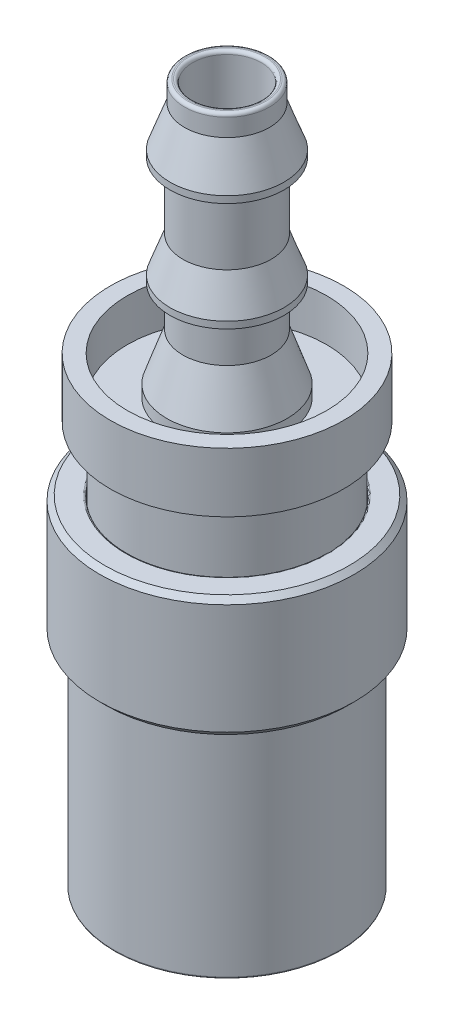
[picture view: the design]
ISO-10303-21;
HEADER;
FILE_DESCRIPTION(('STEP AP214'),'2;1');
FILE_NAME('part.step','',(''),(''),'','','');
FILE_SCHEMA(('AUTOMOTIVE_DESIGN { 1 0 10303 214 1 1 1 1 }'));
ENDSEC;
DATA;
#1=APPLICATION_CONTEXT('core data for automotive mechanical design processes');
#2=APPLICATION_PROTOCOL_DEFINITION('international standard','automotive_design',2000,#1);
#3=PRODUCT_CONTEXT('',#1,'mechanical');
#4=PRODUCT('Part','Part','',(#3));
#5=PRODUCT_RELATED_PRODUCT_CATEGORY('part','',(#4));
#6=PRODUCT_DEFINITION_FORMATION('','',#4);
#7=PRODUCT_DEFINITION_CONTEXT('part definition',#1,'design');
#8=PRODUCT_DEFINITION('design','',#6,#7);
#9=PRODUCT_DEFINITION_SHAPE('','',#8);
#10=(LENGTH_UNIT() NAMED_UNIT(*) SI_UNIT(.MILLI.,.METRE.));
#11=(NAMED_UNIT(*) PLANE_ANGLE_UNIT() SI_UNIT($,.RADIAN.));
#12=(NAMED_UNIT(*) SI_UNIT($,.STERADIAN.) SOLID_ANGLE_UNIT());
#13=UNCERTAINTY_MEASURE_WITH_UNIT(LENGTH_MEASURE(1.E-05),#10,'distance_accuracy_value','');
#14=(GEOMETRIC_REPRESENTATION_CONTEXT(3) GLOBAL_UNCERTAINTY_ASSIGNED_CONTEXT((#13)) GLOBAL_UNIT_ASSIGNED_CONTEXT((#10,
#11,#12)) REPRESENTATION_CONTEXT('',''));
#15=CARTESIAN_POINT('',(0.,0.,0.));
#16=DIRECTION('',(0.,0.,1.));
#17=DIRECTION('',(1.,0.,0.));
#18=AXIS2_PLACEMENT_3D('',#15,#16,#17);
#19=CARTESIAN_POINT('',(0.,25.2095,0.));
#20=DIRECTION('',(0.,-1.,0.));
#21=DIRECTION('',(0.,0.,-1.));
#22=AXIS2_PLACEMENT_3D('',#19,#20,#21);
#23=CONICAL_SURFACE('',#22,9.3345,0.785398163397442);
#24=CARTESIAN_POINT('',(0.,25.4,0.));
#25=DIRECTION('',(0.,-1.,0.));
#26=DIRECTION('',(0.,0.,-1.));
#27=AXIS2_PLACEMENT_3D('',#24,#25,#26);
#28=CIRCLE('',#27,9.144);
#29=CARTESIAN_POINT('',(0.,25.4,9.144));
#30=VERTEX_POINT('',#29);
#31=EDGE_CURVE('P0_E11',#30,#30,#28,.T.);
#32=ORIENTED_EDGE('',*,*,#31,.T.);
#33=DIRECTION('',(0.,-0.707106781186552,0.707106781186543));
#34=VECTOR('',#33,1.);
#35=CARTESIAN_POINT('',(0.,25.2095,9.3345));
#36=LINE('',#35,#34);
#37=CARTESIAN_POINT('',(0.,25.019,9.525));
#38=VERTEX_POINT('',#37);
#39=EDGE_CURVE('P0_E27',#30,#38,#36,.T.);
#40=ORIENTED_EDGE('',*,*,#39,.T.);
#41=CARTESIAN_POINT('',(0.,25.019,0.));
#42=DIRECTION('',(0.,1.,0.));
#43=DIRECTION('',(0.,0.,-1.));
#44=AXIS2_PLACEMENT_3D('',#41,#42,#43);
#45=CIRCLE('',#44,9.525);
#46=CARTESIAN_POINT('',(0.,25.019,-9.525));
#47=VERTEX_POINT('',#46);
#48=EDGE_CURVE('P0_E226',#38,#47,#45,.T.);
#49=ORIENTED_EDGE('',*,*,#48,.T.);
#50=CARTESIAN_POINT('',(0.,25.019,0.));
#51=DIRECTION('',(0.,1.,0.));
#52=DIRECTION('',(0.,0.,-1.));
#53=AXIS2_PLACEMENT_3D('',#50,#51,#52);
#54=CIRCLE('',#53,9.525);
#55=EDGE_CURVE('P0_E207',#47,#38,#54,.T.);
#56=ORIENTED_EDGE('',*,*,#55,.T.);
#57=ORIENTED_EDGE('',*,*,#39,.F.);
#58=EDGE_LOOP('',(#32,#40,#49,#56,#57));
#59=FACE_BOUND('',#58,.T.);
#60=ADVANCED_FACE('P0_F16',(#59),#23,.T.);
#61=CARTESIAN_POINT('',(0.,20.828,0.));
#62=DIRECTION('',(0.,1.,0.));
#63=DIRECTION('',(0.,0.,1.));
#64=AXIS2_PLACEMENT_3D('',#61,#62,#63);
#65=CYLINDRICAL_SURFACE('',#64,9.525);
#66=ORIENTED_EDGE('',*,*,#48,.F.);
#67=ORIENTED_EDGE('',*,*,#55,.F.);
#68=DIRECTION('',(0.,-1.,0.));
#69=VECTOR('',#68,1.);
#70=CARTESIAN_POINT('',(0.,20.828,-9.525));
#71=LINE('',#70,#69);
#72=CARTESIAN_POINT('',(0.,16.764,-9.525));
#73=VERTEX_POINT('',#72);
#74=EDGE_CURVE('P0_E203',#47,#73,#71,.T.);
#75=ORIENTED_EDGE('',*,*,#74,.T.);
#76=CARTESIAN_POINT('',(0.,16.764,0.));
#77=DIRECTION('',(0.,-1.,0.));
#78=DIRECTION('',(0.,0.,-1.));
#79=AXIS2_PLACEMENT_3D('',#76,#77,#78);
#80=CIRCLE('',#79,9.525);
#81=CARTESIAN_POINT('',(0.,16.764,9.525));
#82=VERTEX_POINT('',#81);
#83=EDGE_CURVE('P0_E274',#82,#73,#80,.T.);
#84=ORIENTED_EDGE('',*,*,#83,.F.);
#85=CARTESIAN_POINT('',(0.,16.764,0.));
#86=DIRECTION('',(0.,-1.,0.));
#87=DIRECTION('',(0.,0.,-1.));
#88=AXIS2_PLACEMENT_3D('',#85,#86,#87);
#89=CIRCLE('',#88,9.525);
#90=EDGE_CURVE('P0_E301',#73,#82,#89,.T.);
#91=ORIENTED_EDGE('',*,*,#90,.F.);
#92=ORIENTED_EDGE('',*,*,#74,.F.);
#93=EDGE_LOOP('',(#66,#67,#75,#84,#91,#92));
#94=FACE_BOUND('',#93,.T.);
#95=ADVANCED_FACE('P0_F344',(#94),#65,.T.);
#96=CARTESIAN_POINT('',(0.,25.4,7.4549));
#97=DIRECTION('',(0.,1.,0.));
#98=DIRECTION('',(1.,0.,0.));
#99=AXIS2_PLACEMENT_3D('',#96,#97,#98);
#100=PLANE('',#99);
#101=ORIENTED_EDGE('',*,*,#31,.F.);
#102=EDGE_LOOP('',(#101));
#103=FACE_BOUND('',#102,.T.);
#104=CARTESIAN_POINT('',(0.,25.4,0.));
#105=DIRECTION('',(0.,1.,0.));
#106=DIRECTION('',(0.,0.,-1.));
#107=AXIS2_PLACEMENT_3D('',#104,#105,#106);
#108=CIRCLE('',#107,7.5819);
#109=CARTESIAN_POINT('',(0.,25.4,-7.5819));
#110=VERTEX_POINT('',#109);
#111=EDGE_CURVE('P0_E138',#110,#110,#108,.T.);
#112=ORIENTED_EDGE('',*,*,#111,.F.);
#113=EDGE_LOOP('',(#112));
#114=FACE_BOUND('',#113,.T.);
#115=ADVANCED_FACE('P0_F139',(#103,#114),#100,.T.);
#116=CARTESIAN_POINT('',(0.,6.096,0.));
#117=DIRECTION('',(0.,1.,0.));
#118=DIRECTION('',(0.,0.,1.));
#119=AXIS2_PLACEMENT_3D('',#116,#117,#118);
#120=TOROIDAL_SURFACE('',#119,6.6802,0.254);
#121=CARTESIAN_POINT('',(0.,6.096,0.));
#122=DIRECTION('',(0.,-1.,0.));
#123=DIRECTION('',(0.,0.,-1.));
#124=AXIS2_PLACEMENT_3D('',#121,#122,#123);
#125=CIRCLE('',#124,6.4262);
#126=CARTESIAN_POINT('',(0.,6.096,6.4262));
#127=VERTEX_POINT('',#126);
#128=CARTESIAN_POINT('',(0.,6.096,-6.4262));
#129=VERTEX_POINT('',#128);
#130=EDGE_CURVE('P0_E208',#127,#129,#125,.T.);
#131=ORIENTED_EDGE('',*,*,#130,.T.);
#132=CARTESIAN_POINT('',(0.,6.096,-6.6802));
#133=DIRECTION('',(-1.,0.,0.));
#134=DIRECTION('',(0.,0.,-1.));
#135=AXIS2_PLACEMENT_3D('',#132,#133,#134);
#136=CIRCLE('',#135,0.254);
#137=CARTESIAN_POINT('',(0.,6.35,-6.6802));
#138=VERTEX_POINT('',#137);
#139=EDGE_CURVE('P0_E253',#129,#138,#136,.T.);
#140=ORIENTED_EDGE('',*,*,#139,.T.);
#141=CARTESIAN_POINT('',(0.,6.35,0.));
#142=DIRECTION('',(0.,1.,0.));
#143=DIRECTION('',(0.,0.,-1.));
#144=AXIS2_PLACEMENT_3D('',#141,#142,#143);
#145=CIRCLE('',#144,6.6802);
#146=CARTESIAN_POINT('',(0.,6.35,6.6802));
#147=VERTEX_POINT('',#146);
#148=EDGE_CURVE('P0_E248',#138,#147,#145,.T.);
#149=ORIENTED_EDGE('',*,*,#148,.T.);
#150=CARTESIAN_POINT('',(0.,6.35,0.));
#151=DIRECTION('',(0.,1.,0.));
#152=DIRECTION('',(0.,0.,-1.));
#153=AXIS2_PLACEMENT_3D('',#150,#151,#152);
#154=CIRCLE('',#153,6.6802);
#155=EDGE_CURVE('P0_E244',#147,#138,#154,.T.);
#156=ORIENTED_EDGE('',*,*,#155,.T.);
#157=ORIENTED_EDGE('',*,*,#139,.F.);
#158=CARTESIAN_POINT('',(0.,6.096,0.));
#159=DIRECTION('',(0.,-1.,0.));
#160=DIRECTION('',(0.,0.,-1.));
#161=AXIS2_PLACEMENT_3D('',#158,#159,#160);
#162=CIRCLE('',#161,6.4262);
#163=EDGE_CURVE('P0_E249',#129,#127,#162,.T.);
#164=ORIENTED_EDGE('',*,*,#163,.T.);
#165=EDGE_LOOP('',(#131,#140,#149,#156,#157,#164));
#166=FACE_BOUND('',#165,.T.);
#167=ADVANCED_FACE('P0_F18',(#166),#120,.T.);
#168=CARTESIAN_POINT('',(0.,6.35,6.4262));
#169=DIRECTION('',(0.,1.,0.));
#170=DIRECTION('',(1.,0.,0.));
#171=AXIS2_PLACEMENT_3D('',#168,#169,#170);
#172=PLANE('',#171);
#173=CARTESIAN_POINT('',(0.,6.35,0.));
#174=DIRECTION('',(0.,-1.,0.));
#175=DIRECTION('',(0.,0.,-1.));
#176=AXIS2_PLACEMENT_3D('',#173,#174,#175);
#177=CIRCLE('',#176,7.2009);
#178=CARTESIAN_POINT('',(0.,6.35,7.2009));
#179=VERTEX_POINT('',#178);
#180=CARTESIAN_POINT('',(0.,6.35,-7.2009));
#181=VERTEX_POINT('',#180);
#182=EDGE_CURVE('P0_E202',#179,#181,#177,.T.);
#183=ORIENTED_EDGE('',*,*,#182,.F.);
#184=CARTESIAN_POINT('',(0.,6.35,0.));
#185=DIRECTION('',(0.,-1.,0.));
#186=DIRECTION('',(0.,0.,-1.));
#187=AXIS2_PLACEMENT_3D('',#184,#185,#186);
#188=CIRCLE('',#187,7.2009);
#189=EDGE_CURVE('P0_E198',#181,#179,#188,.T.);
#190=ORIENTED_EDGE('',*,*,#189,.F.);
#191=EDGE_LOOP('',(#183,#190));
#192=FACE_BOUND('',#191,.T.);
#193=ORIENTED_EDGE('',*,*,#155,.F.);
#194=ORIENTED_EDGE('',*,*,#148,.F.);
#195=EDGE_LOOP('',(#193,#194));
#196=FACE_BOUND('',#195,.T.);
#197=ADVANCED_FACE('P0_F440',(#192,#196),#172,.T.);
#198=CARTESIAN_POINT('',(0.,4.1402,0.));
#199=DIRECTION('',(0.,1.,0.));
#200=DIRECTION('',(0.,0.,1.));
#201=AXIS2_PLACEMENT_3D('',#198,#199,#200);
#202=CYLINDRICAL_SURFACE('',#201,6.4262);
#203=ORIENTED_EDGE('',*,*,#130,.F.);
#204=ORIENTED_EDGE('',*,*,#163,.F.);
#205=DIRECTION('',(0.,-1.,0.));
#206=VECTOR('',#205,1.);
#207=CARTESIAN_POINT('',(0.,4.1402,-6.4262));
#208=LINE('',#207,#206);
#209=CARTESIAN_POINT('',(0.,1.9304,-6.4262));
#210=VERTEX_POINT('',#209);
#211=EDGE_CURVE('P0_E288',#129,#210,#208,.T.);
#212=ORIENTED_EDGE('',*,*,#211,.T.);
#213=CARTESIAN_POINT('',(0.,1.9304,0.));
#214=DIRECTION('',(0.,1.,0.));
#215=DIRECTION('',(1.,0.,0.));
#216=AXIS2_PLACEMENT_3D('',#213,#214,#215);
#217=CIRCLE('',#216,6.4262);
#218=CARTESIAN_POINT('',(0.,1.9304,6.4262));
#219=VERTEX_POINT('',#218);
#220=EDGE_CURVE('P0_E254',#219,#210,#217,.T.);
#221=ORIENTED_EDGE('',*,*,#220,.F.);
#222=CARTESIAN_POINT('',(0.,1.9304,0.));
#223=DIRECTION('',(0.,1.,0.));
#224=DIRECTION('',(1.,0.,0.));
#225=AXIS2_PLACEMENT_3D('',#222,#223,#224);
#226=CIRCLE('',#225,6.4262);
#227=EDGE_CURVE('P0_E209',#210,#219,#226,.T.);
#228=ORIENTED_EDGE('',*,*,#227,.F.);
#229=ORIENTED_EDGE('',*,*,#211,.F.);
#230=EDGE_LOOP('',(#203,#204,#212,#221,#228,#229));
#231=FACE_BOUND('',#230,.T.);
#232=ADVANCED_FACE('P0_F420',(#231),#202,.F.);
#233=CARTESIAN_POINT('',(0.,6.604,0.));
#234=DIRECTION('',(0.,1.,0.));
#235=DIRECTION('',(0.,0.,1.));
#236=AXIS2_PLACEMENT_3D('',#233,#234,#235);
#237=TOROIDAL_SURFACE('',#236,7.2009,0.254);
#238=CARTESIAN_POINT('',(0.,6.604,0.));
#239=DIRECTION('',(0.,1.,0.));
#240=DIRECTION('',(0.,0.,-1.));
#241=AXIS2_PLACEMENT_3D('',#238,#239,#240);
#242=CIRCLE('',#241,7.4549);
#243=CARTESIAN_POINT('',(0.,6.604,7.4549));
#244=VERTEX_POINT('',#243);
#245=CARTESIAN_POINT('',(0.,6.604,-7.4549));
#246=VERTEX_POINT('',#245);
#247=EDGE_CURVE('P0_E285',#244,#246,#242,.T.);
#248=ORIENTED_EDGE('',*,*,#247,.T.);
#249=CARTESIAN_POINT('',(0.,6.604,-7.2009));
#250=DIRECTION('',(-1.,0.,0.));
#251=DIRECTION('',(0.,0.,-1.));
#252=AXIS2_PLACEMENT_3D('',#249,#250,#251);
#253=CIRCLE('',#252,0.254);
#254=EDGE_CURVE('P0_E201',#246,#181,#253,.T.);
#255=ORIENTED_EDGE('',*,*,#254,.T.);
#256=ORIENTED_EDGE('',*,*,#189,.T.);
#257=ORIENTED_EDGE('',*,*,#182,.T.);
#258=ORIENTED_EDGE('',*,*,#254,.F.);
#259=CARTESIAN_POINT('',(0.,6.604,0.));
#260=DIRECTION('',(0.,1.,0.));
#261=DIRECTION('',(0.,0.,-1.));
#262=AXIS2_PLACEMENT_3D('',#259,#260,#261);
#263=CIRCLE('',#262,7.4549);
#264=EDGE_CURVE('P0_E281',#246,#244,#263,.T.);
#265=ORIENTED_EDGE('',*,*,#264,.T.);
#266=EDGE_LOOP('',(#248,#255,#256,#257,#258,#265));
#267=FACE_BOUND('',#266,.T.);
#268=ADVANCED_FACE('P0_F413',(#267),#237,.F.);
#269=CARTESIAN_POINT('',(0.,15.875,0.));
#270=DIRECTION('',(0.,1.,0.));
#271=DIRECTION('',(0.,0.,1.));
#272=AXIS2_PLACEMENT_3D('',#269,#270,#271);
#273=CYLINDRICAL_SURFACE('',#272,7.4549);
#274=CARTESIAN_POINT('',(0.,25.273,0.));
#275=DIRECTION('',(0.,-1.,0.));
#276=DIRECTION('',(0.,0.,-1.));
#277=AXIS2_PLACEMENT_3D('',#274,#275,#276);
#278=CIRCLE('',#277,7.4549);
#279=CARTESIAN_POINT('',(0.,25.273,7.4549));
#280=VERTEX_POINT('',#279);
#281=CARTESIAN_POINT('',(0.,25.273,-7.4549));
#282=VERTEX_POINT('',#281);
#283=EDGE_CURVE('P0_E151',#280,#282,#278,.T.);
#284=ORIENTED_EDGE('',*,*,#283,.F.);
#285=CARTESIAN_POINT('',(0.,25.273,0.));
#286=DIRECTION('',(0.,-1.,0.));
#287=DIRECTION('',(0.,0.,-1.));
#288=AXIS2_PLACEMENT_3D('',#285,#286,#287);
#289=CIRCLE('',#288,7.4549);
#290=EDGE_CURVE('P0_E145',#282,#280,#289,.T.);
#291=ORIENTED_EDGE('',*,*,#290,.F.);
#292=DIRECTION('',(0.,-1.,0.));
#293=VECTOR('',#292,1.);
#294=CARTESIAN_POINT('',(0.,15.875,-7.4549));
#295=LINE('',#294,#293);
#296=EDGE_CURVE('P0_E277',#282,#246,#295,.T.);
#297=ORIENTED_EDGE('',*,*,#296,.T.);
#298=ORIENTED_EDGE('',*,*,#247,.F.);
#299=ORIENTED_EDGE('',*,*,#264,.F.);
#300=ORIENTED_EDGE('',*,*,#296,.F.);
#301=EDGE_LOOP('',(#284,#291,#297,#298,#299,#300));
#302=FACE_BOUND('',#301,.T.);
#303=ADVANCED_FACE('P0_F419',(#302),#273,.F.);
#304=CARTESIAN_POINT('',(0.,16.51,0.));
#305=DIRECTION('',(0.,1.,0.));
#306=DIRECTION('',(0.,0.,-1.));
#307=AXIS2_PLACEMENT_3D('',#304,#305,#306);
#308=CONICAL_SURFACE('',#307,9.271,0.785398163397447);
#309=ORIENTED_EDGE('',*,*,#83,.T.);
#310=ORIENTED_EDGE('',*,*,#90,.T.);
#311=DIRECTION('',(0.,-0.707106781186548,-0.707106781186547));
#312=VECTOR('',#311,1.);
#313=CARTESIAN_POINT('',(0.,16.51,9.271));
#314=LINE('',#313,#312);
#315=CARTESIAN_POINT('',(0.,16.256,9.017));
#316=VERTEX_POINT('',#315);
#317=EDGE_CURVE('P0_E303',#82,#316,#314,.T.);
#318=ORIENTED_EDGE('',*,*,#317,.T.);
#319=CARTESIAN_POINT('',(0.,16.256,0.));
#320=DIRECTION('',(0.,1.,0.));
#321=DIRECTION('',(0.,0.,-1.));
#322=AXIS2_PLACEMENT_3D('',#319,#320,#321);
#323=CIRCLE('',#322,9.017);
#324=EDGE_CURVE('P0_E233',#316,#316,#323,.T.);
#325=ORIENTED_EDGE('',*,*,#324,.T.);
#326=ORIENTED_EDGE('',*,*,#317,.F.);
#327=EDGE_LOOP('',(#309,#310,#318,#325,#326));
#328=FACE_BOUND('',#327,.T.);
#329=ADVANCED_FACE('P0_F321',(#328),#308,.T.);
#330=CARTESIAN_POINT('',(0.,16.256,9.525));
#331=DIRECTION('',(0.,-1.,0.));
#332=DIRECTION('',(0.,0.,-1.));
#333=AXIS2_PLACEMENT_3D('',#330,#331,#332);
#334=PLANE('',#333);
#335=ORIENTED_EDGE('',*,*,#324,.F.);
#336=EDGE_LOOP('',(#335));
#337=FACE_BOUND('',#336,.T.);
#338=CARTESIAN_POINT('',(0.,16.256,0.));
#339=DIRECTION('',(0.,1.,0.));
#340=DIRECTION('',(1.,0.,0.));
#341=AXIS2_PLACEMENT_3D('',#338,#339,#340);
#342=CIRCLE('',#341,8.4328);
#343=CARTESIAN_POINT('',(0.,16.256,8.4328));
#344=VERTEX_POINT('',#343);
#345=CARTESIAN_POINT('',(0.,16.256,-8.4328));
#346=VERTEX_POINT('',#345);
#347=EDGE_CURVE('P0_E230',#344,#346,#342,.T.);
#348=ORIENTED_EDGE('',*,*,#347,.T.);
#349=CARTESIAN_POINT('',(0.,16.256,0.));
#350=DIRECTION('',(0.,1.,0.));
#351=DIRECTION('',(1.,0.,0.));
#352=AXIS2_PLACEMENT_3D('',#349,#350,#351);
#353=CIRCLE('',#352,8.4328);
#354=EDGE_CURVE('P0_E234',#346,#344,#353,.T.);
#355=ORIENTED_EDGE('',*,*,#354,.T.);
#356=EDGE_LOOP('',(#348,#355));
#357=FACE_BOUND('',#356,.T.);
#358=ADVANCED_FACE('P0_F324',(#337,#357),#334,.T.);
#359=CARTESIAN_POINT('',(0.,0.127,0.));
#360=DIRECTION('',(0.,1.,0.));
#361=DIRECTION('',(0.,0.,1.));
#362=AXIS2_PLACEMENT_3D('',#359,#360,#361);
#363=TOROIDAL_SURFACE('',#362,8.3058,0.127);
#364=CARTESIAN_POINT('',(0.,0.127,0.));
#365=DIRECTION('',(0.,-1.,0.));
#366=DIRECTION('',(0.,0.,-1.));
#367=AXIS2_PLACEMENT_3D('',#364,#365,#366);
#368=CIRCLE('',#367,8.4328);
#369=CARTESIAN_POINT('',(0.,0.127,8.4328));
#370=VERTEX_POINT('',#369);
#371=CARTESIAN_POINT('',(0.,0.127,-8.4328));
#372=VERTEX_POINT('',#371);
#373=EDGE_CURVE('P0_E243',#370,#372,#368,.T.);
#374=ORIENTED_EDGE('',*,*,#373,.T.);
#375=CARTESIAN_POINT('',(0.,0.127,-8.3058));
#376=DIRECTION('',(-1.,0.,0.));
#377=DIRECTION('',(0.,0.,-1.));
#378=AXIS2_PLACEMENT_3D('',#375,#376,#377);
#379=CIRCLE('',#378,0.127);
#380=CARTESIAN_POINT('',(0.,0.,-8.3058));
#381=VERTEX_POINT('',#380);
#382=EDGE_CURVE('P0_E192',#372,#381,#379,.T.);
#383=ORIENTED_EDGE('',*,*,#382,.T.);
#384=CARTESIAN_POINT('',(0.,0.,0.));
#385=DIRECTION('',(0.,1.,0.));
#386=DIRECTION('',(0.,0.,-1.));
#387=AXIS2_PLACEMENT_3D('',#384,#385,#386);
#388=CIRCLE('',#387,8.3058);
#389=CARTESIAN_POINT('',(0.,0.,8.3058));
#390=VERTEX_POINT('',#389);
#391=EDGE_CURVE('P0_E185',#381,#390,#388,.T.);
#392=ORIENTED_EDGE('',*,*,#391,.T.);
#393=CARTESIAN_POINT('',(0.,0.,0.));
#394=DIRECTION('',(0.,1.,0.));
#395=DIRECTION('',(0.,0.,-1.));
#396=AXIS2_PLACEMENT_3D('',#393,#394,#395);
#397=CIRCLE('',#396,8.3058);
#398=EDGE_CURVE('P0_E177',#390,#381,#397,.T.);
#399=ORIENTED_EDGE('',*,*,#398,.T.);
#400=ORIENTED_EDGE('',*,*,#382,.F.);
#401=CARTESIAN_POINT('',(0.,0.127,0.));
#402=DIRECTION('',(0.,-1.,0.));
#403=DIRECTION('',(0.,0.,-1.));
#404=AXIS2_PLACEMENT_3D('',#401,#402,#403);
#405=CIRCLE('',#404,8.4328);
#406=EDGE_CURVE('P0_E159',#372,#370,#405,.T.);
#407=ORIENTED_EDGE('',*,*,#406,.T.);
#408=EDGE_LOOP('',(#374,#383,#392,#399,#400,#407));
#409=FACE_BOUND('',#408,.T.);
#410=ADVANCED_FACE('P0_F327',(#409),#363,.T.);
#411=CARTESIAN_POINT('',(0.,0.,8.4328));
#412=DIRECTION('',(0.,-1.,0.));
#413=DIRECTION('',(0.,0.,-1.));
#414=AXIS2_PLACEMENT_3D('',#411,#412,#413);
#415=PLANE('',#414);
#416=ORIENTED_EDGE('',*,*,#398,.F.);
#417=ORIENTED_EDGE('',*,*,#391,.F.);
#418=EDGE_LOOP('',(#416,#417));
#419=FACE_BOUND('',#418,.T.);
#420=CARTESIAN_POINT('',(0.,0.,0.));
#421=DIRECTION('',(0.,-1.,0.));
#422=DIRECTION('',(0.,0.,-1.));
#423=AXIS2_PLACEMENT_3D('',#420,#421,#422);
#424=CIRCLE('',#423,7.4422);
#425=CARTESIAN_POINT('',(0.,0.,7.4422));
#426=VERTEX_POINT('',#425);
#427=CARTESIAN_POINT('',(0.,0.,-7.4422));
#428=VERTEX_POINT('',#427);
#429=EDGE_CURVE('P0_E155',#426,#428,#424,.T.);
#430=ORIENTED_EDGE('',*,*,#429,.F.);
#431=CARTESIAN_POINT('',(0.,0.,0.));
#432=DIRECTION('',(0.,-1.,0.));
#433=DIRECTION('',(0.,0.,-1.));
#434=AXIS2_PLACEMENT_3D('',#431,#432,#433);
#435=CIRCLE('',#434,7.4422);
#436=EDGE_CURVE('P0_E196',#428,#426,#435,.T.);
#437=ORIENTED_EDGE('',*,*,#436,.F.);
#438=EDGE_LOOP('',(#430,#437));
#439=FACE_BOUND('',#438,.T.);
#440=ADVANCED_FACE('P0_F334',(#419,#439),#415,.T.);
#441=CARTESIAN_POINT('',(0.,8.128,0.));
#442=DIRECTION('',(0.,1.,0.));
#443=DIRECTION('',(0.,0.,1.));
#444=AXIS2_PLACEMENT_3D('',#441,#442,#443);
#445=CYLINDRICAL_SURFACE('',#444,8.4328);
#446=ORIENTED_EDGE('',*,*,#347,.F.);
#447=ORIENTED_EDGE('',*,*,#354,.F.);
#448=DIRECTION('',(0.,-1.,0.));
#449=VECTOR('',#448,1.);
#450=CARTESIAN_POINT('',(0.,8.128,-8.4328));
#451=LINE('',#450,#449);
#452=EDGE_CURVE('P0_E20',#346,#372,#451,.T.);
#453=ORIENTED_EDGE('',*,*,#452,.T.);
#454=ORIENTED_EDGE('',*,*,#373,.F.);
#455=ORIENTED_EDGE('',*,*,#406,.F.);
#456=ORIENTED_EDGE('',*,*,#452,.F.);
#457=EDGE_LOOP('',(#446,#447,#453,#454,#455,#456));
#458=FACE_BOUND('',#457,.T.);
#459=ADVANCED_FACE('P0_F332',(#458),#445,.T.);
#460=CARTESIAN_POINT('',(0.,25.273,0.));
#461=DIRECTION('',(0.,1.,0.));
#462=DIRECTION('',(0.,0.,1.));
#463=AXIS2_PLACEMENT_3D('',#460,#461,#462);
#464=TOROIDAL_SURFACE('',#463,7.5819,0.127);
#465=ORIENTED_EDGE('',*,*,#283,.T.);
#466=CARTESIAN_POINT('',(0.,25.273,-7.5819));
#467=DIRECTION('',(-1.,0.,0.));
#468=DIRECTION('',(0.,0.,-1.));
#469=AXIS2_PLACEMENT_3D('',#466,#467,#468);
#470=CIRCLE('',#469,0.127);
#471=EDGE_CURVE('P0_E144',#282,#110,#470,.T.);
#472=ORIENTED_EDGE('',*,*,#471,.T.);
#473=ORIENTED_EDGE('',*,*,#111,.T.);
#474=ORIENTED_EDGE('',*,*,#471,.F.);
#475=ORIENTED_EDGE('',*,*,#290,.T.);
#476=EDGE_LOOP('',(#465,#472,#473,#474,#475));
#477=FACE_BOUND('',#476,.T.);
#478=ADVANCED_FACE('P0_F357',(#477),#464,.T.);
#479=CARTESIAN_POINT('',(0.,0.127,0.));
#480=DIRECTION('',(0.,1.,0.));
#481=DIRECTION('',(0.,0.,1.));
#482=AXIS2_PLACEMENT_3D('',#479,#480,#481);
#483=TOROIDAL_SURFACE('',#482,7.4422,0.127);
#484=ORIENTED_EDGE('',*,*,#429,.T.);
#485=CARTESIAN_POINT('',(0.,0.127,-7.4422));
#486=DIRECTION('',(-1.,0.,0.));
#487=DIRECTION('',(0.,0.,-1.));
#488=AXIS2_PLACEMENT_3D('',#485,#486,#487);
#489=CIRCLE('',#488,0.127);
#490=CARTESIAN_POINT('',(0.,0.127,-7.3152));
#491=VERTEX_POINT('',#490);
#492=EDGE_CURVE('P0_E163',#428,#491,#489,.T.);
#493=ORIENTED_EDGE('',*,*,#492,.T.);
#494=CARTESIAN_POINT('',(0.,0.127,0.));
#495=DIRECTION('',(0.,1.,0.));
#496=DIRECTION('',(0.,0.,-1.));
#497=AXIS2_PLACEMENT_3D('',#494,#495,#496);
#498=CIRCLE('',#497,7.3152);
#499=CARTESIAN_POINT('',(0.,0.127,7.3152));
#500=VERTEX_POINT('',#499);
#501=EDGE_CURVE('P0_E217',#491,#500,#498,.T.);
#502=ORIENTED_EDGE('',*,*,#501,.T.);
#503=CARTESIAN_POINT('',(0.,0.127,0.));
#504=DIRECTION('',(0.,1.,0.));
#505=DIRECTION('',(0.,0.,-1.));
#506=AXIS2_PLACEMENT_3D('',#503,#504,#505);
#507=CIRCLE('',#506,7.3152);
#508=EDGE_CURVE('P0_E214',#500,#491,#507,.T.);
#509=ORIENTED_EDGE('',*,*,#508,.T.);
#510=ORIENTED_EDGE('',*,*,#492,.F.);
#511=ORIENTED_EDGE('',*,*,#436,.T.);
#512=EDGE_LOOP('',(#484,#493,#502,#509,#510,#511));
#513=FACE_BOUND('',#512,.T.);
#514=ADVANCED_FACE('P0_F353',(#513),#483,.T.);
#515=CARTESIAN_POINT('',(0.,0.5207,0.));
#516=DIRECTION('',(0.,1.,0.));
#517=DIRECTION('',(0.,0.,1.));
#518=AXIS2_PLACEMENT_3D('',#515,#516,#517);
#519=CYLINDRICAL_SURFACE('',#518,7.3152);
#520=CARTESIAN_POINT('',(0.,1.0414,0.));
#521=DIRECTION('',(0.,1.,0.));
#522=DIRECTION('',(1.,0.,0.));
#523=AXIS2_PLACEMENT_3D('',#520,#521,#522);
#524=CIRCLE('',#523,7.3152);
#525=CARTESIAN_POINT('',(0.,1.0414,7.3152));
#526=VERTEX_POINT('',#525);
#527=CARTESIAN_POINT('',(0.,1.0414,-7.3152));
#528=VERTEX_POINT('',#527);
#529=EDGE_CURVE('P0_E218',#526,#528,#524,.T.);
#530=ORIENTED_EDGE('',*,*,#529,.T.);
#531=DIRECTION('',(0.,-1.,0.));
#532=VECTOR('',#531,1.);
#533=CARTESIAN_POINT('',(0.,0.5207,-7.3152));
#534=LINE('',#533,#532);
#535=EDGE_CURVE('P0_E222',#528,#491,#534,.T.);
#536=ORIENTED_EDGE('',*,*,#535,.T.);
#537=ORIENTED_EDGE('',*,*,#508,.F.);
#538=ORIENTED_EDGE('',*,*,#501,.F.);
#539=ORIENTED_EDGE('',*,*,#535,.F.);
#540=CARTESIAN_POINT('',(0.,1.0414,0.));
#541=DIRECTION('',(0.,1.,0.));
#542=DIRECTION('',(1.,0.,0.));
#543=AXIS2_PLACEMENT_3D('',#540,#541,#542);
#544=CIRCLE('',#543,7.3152);
#545=EDGE_CURVE('P0_E239',#528,#526,#544,.T.);
#546=ORIENTED_EDGE('',*,*,#545,.T.);
#547=EDGE_LOOP('',(#530,#536,#537,#538,#539,#546));
#548=FACE_BOUND('',#547,.T.);
#549=ADVANCED_FACE('P0_F356',(#548),#519,.F.);
#550=CARTESIAN_POINT('',(0.,1.4859,0.));
#551=DIRECTION('',(0.,-1.,0.));
#552=DIRECTION('',(0.,0.,1.));
#553=AXIS2_PLACEMENT_3D('',#550,#551,#552);
#554=CONICAL_SURFACE('',#553,6.8707,0.78539816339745);
#555=ORIENTED_EDGE('',*,*,#220,.T.);
#556=DIRECTION('',(0.,-0.707106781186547,-0.707106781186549));
#557=VECTOR('',#556,1.);
#558=CARTESIAN_POINT('',(0.,1.4859,-6.8707));
#559=LINE('',#558,#557);
#560=EDGE_CURVE('P0_E213',#210,#528,#559,.T.);
#561=ORIENTED_EDGE('',*,*,#560,.T.);
#562=ORIENTED_EDGE('',*,*,#529,.F.);
#563=ORIENTED_EDGE('',*,*,#545,.F.);
#564=ORIENTED_EDGE('',*,*,#560,.F.);
#565=ORIENTED_EDGE('',*,*,#227,.T.);
#566=EDGE_LOOP('',(#555,#561,#562,#563,#564,#565));
#567=FACE_BOUND('',#566,.T.);
#568=ADVANCED_FACE('P0_F387',(#567),#554,.F.);
#569=CLOSED_SHELL('',(#60,#95,#115,#167,#197,#232,#268,#303,#329,#358,#410,#440,#459,#478,#514,
#549,#568));
#570=MANIFOLD_SOLID_BREP('P0_B1',#569);
#571=CARTESIAN_POINT('',(0.,52.121054,0.));
#572=DIRECTION('',(0.,-1.,0.));
#573=DIRECTION('',(0.,0.,-1.));
#574=AXIS2_PLACEMENT_3D('',#571,#572,#573);
#575=TOROIDAL_SURFACE('',#574,2.83209999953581,0.254);
#576=CARTESIAN_POINT('',(0.,52.375054,0.));
#577=DIRECTION('',(0.,1.,0.));
#578=DIRECTION('',(0.,0.,1.));
#579=AXIS2_PLACEMENT_3D('',#576,#577,#578);
#580=CIRCLE('',#579,2.83209999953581);
#581=CARTESIAN_POINT('',(0.,52.375054,-2.83209999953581));
#582=VERTEX_POINT('',#581);
#583=CARTESIAN_POINT('',(0.,52.375054,2.83209999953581));
#584=VERTEX_POINT('',#583);
#585=EDGE_CURVE('P1_E11',#582,#584,#580,.T.);
#586=ORIENTED_EDGE('',*,*,#585,.T.);
#587=CARTESIAN_POINT('',(0.,52.121054,2.83209999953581));
#588=DIRECTION('',(-1.,0.,0.));
#589=DIRECTION('',(0.,0.,1.));
#590=AXIS2_PLACEMENT_3D('',#587,#588,#589);
#591=CIRCLE('',#590,0.254);
#592=CARTESIAN_POINT('',(0.,52.121054,2.57809999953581));
#593=VERTEX_POINT('',#592);
#594=EDGE_CURVE('P1_E20',#584,#593,#591,.T.);
#595=ORIENTED_EDGE('',*,*,#594,.T.);
#596=CARTESIAN_POINT('',(0.,52.121054,0.));
#597=DIRECTION('',(0.,-1.,0.));
#598=DIRECTION('',(0.,0.,1.));
#599=AXIS2_PLACEMENT_3D('',#596,#597,#598);
#600=CIRCLE('',#599,2.57809999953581);
#601=CARTESIAN_POINT('',(0.,52.121054,-2.57809999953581));
#602=VERTEX_POINT('',#601);
#603=EDGE_CURVE('P1_E94',#593,#602,#600,.T.);
#604=ORIENTED_EDGE('',*,*,#603,.T.);
#605=CARTESIAN_POINT('',(0.,52.121054,0.));
#606=DIRECTION('',(0.,-1.,0.));
#607=DIRECTION('',(0.,0.,1.));
#608=AXIS2_PLACEMENT_3D('',#605,#606,#607);
#609=CIRCLE('',#608,2.57809999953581);
#610=EDGE_CURVE('P1_E96',#602,#593,#609,.T.);
#611=ORIENTED_EDGE('',*,*,#610,.T.);
#612=ORIENTED_EDGE('',*,*,#594,.F.);
#613=CARTESIAN_POINT('',(0.,52.375054,0.));
#614=DIRECTION('',(0.,1.,0.));
#615=DIRECTION('',(0.,0.,1.));
#616=AXIS2_PLACEMENT_3D('',#613,#614,#615);
#617=CIRCLE('',#616,2.83209999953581);
#618=EDGE_CURVE('P1_E106',#584,#582,#617,.T.);
#619=ORIENTED_EDGE('',*,*,#618,.T.);
#620=EDGE_LOOP('',(#586,#595,#604,#611,#612,#619));
#621=FACE_BOUND('',#620,.T.);
#622=ADVANCED_FACE('P1_F16',(#621),#575,.T.);
#623=CARTESIAN_POINT('',(0.,52.375054,-3.17492378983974));
#624=DIRECTION('',(0.,1.,0.));
#625=DIRECTION('',(1.,0.,0.));
#626=AXIS2_PLACEMENT_3D('',#623,#624,#625);
#627=PLANE('',#626);
#628=CARTESIAN_POINT('',(0.,52.375054,0.));
#629=DIRECTION('',(0.,-1.,0.));
#630=DIRECTION('',(0.,0.,1.));
#631=AXIS2_PLACEMENT_3D('',#628,#629,#630);
#632=CIRCLE('',#631,2.92092378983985);
#633=CARTESIAN_POINT('',(0.,52.375054,-2.92092378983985));
#634=VERTEX_POINT('',#633);
#635=CARTESIAN_POINT('',(0.,52.375054,2.92092378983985));
#636=VERTEX_POINT('',#635);
#637=EDGE_CURVE('P1_E181',#634,#636,#632,.T.);
#638=ORIENTED_EDGE('',*,*,#637,.F.);
#639=CARTESIAN_POINT('',(0.,52.375054,0.));
#640=DIRECTION('',(0.,-1.,0.));
#641=DIRECTION('',(0.,0.,1.));
#642=AXIS2_PLACEMENT_3D('',#639,#640,#641);
#643=CIRCLE('',#642,2.92092378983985);
#644=EDGE_CURVE('P1_E176',#636,#634,#643,.T.);
#645=ORIENTED_EDGE('',*,*,#644,.F.);
#646=EDGE_LOOP('',(#638,#645));
#647=FACE_BOUND('',#646,.T.);
#648=ORIENTED_EDGE('',*,*,#585,.F.);
#649=ORIENTED_EDGE('',*,*,#618,.F.);
#650=EDGE_LOOP('',(#648,#649));
#651=FACE_BOUND('',#650,.T.);
#652=ADVANCED_FACE('P1_F657',(#647,#651),#627,.T.);
#653=CARTESIAN_POINT('',(0.,39.674927,0.));
#654=DIRECTION('',(0.,-1.,0.));
#655=DIRECTION('',(0.,0.,-1.));
#656=AXIS2_PLACEMENT_3D('',#653,#654,#655);
#657=CYLINDRICAL_SURFACE('',#656,2.57809999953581);
#658=CARTESIAN_POINT('',(0.,26.9748,0.));
#659=DIRECTION('',(0.,-1.,0.));
#660=DIRECTION('',(1.,0.,0.));
#661=AXIS2_PLACEMENT_3D('',#658,#659,#660);
#662=CIRCLE('',#661,2.5780999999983);
#663=CARTESIAN_POINT('',(0.,26.9748,-2.5780999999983));
#664=VERTEX_POINT('',#663);
#665=CARTESIAN_POINT('',(0.,26.9748,2.57809999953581));
#666=VERTEX_POINT('',#665);
#667=EDGE_CURVE('P1_E112',#664,#666,#662,.T.);
#668=ORIENTED_EDGE('',*,*,#667,.T.);
#669=DIRECTION('',(0.,1.,0.));
#670=VECTOR('',#669,1.);
#671=CARTESIAN_POINT('',(0.,39.674927,2.57809999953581));
#672=LINE('',#671,#670);
#673=EDGE_CURVE('P1_E104',#666,#593,#672,.T.);
#674=ORIENTED_EDGE('',*,*,#673,.T.);
#675=ORIENTED_EDGE('',*,*,#610,.F.);
#676=ORIENTED_EDGE('',*,*,#603,.F.);
#677=ORIENTED_EDGE('',*,*,#673,.F.);
#678=CARTESIAN_POINT('',(0.,26.9748,0.));
#679=DIRECTION('',(0.,-1.,0.));
#680=DIRECTION('',(1.,0.,0.));
#681=AXIS2_PLACEMENT_3D('',#678,#679,#680);
#682=CIRCLE('',#681,2.5780999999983);
#683=EDGE_CURVE('P1_E264',#666,#664,#682,.T.);
#684=ORIENTED_EDGE('',*,*,#683,.T.);
#685=EDGE_LOOP('',(#668,#674,#675,#676,#677,#684));
#686=FACE_BOUND('',#685,.T.);
#687=ADVANCED_FACE('P1_F103',(#686),#657,.F.);
#688=CARTESIAN_POINT('',(0.,52.121054,0.));
#689=DIRECTION('',(0.,-1.,0.));
#690=DIRECTION('',(0.,0.,-1.));
#691=AXIS2_PLACEMENT_3D('',#688,#689,#690);
#692=TOROIDAL_SURFACE('',#691,2.92092378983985,0.254);
#693=CARTESIAN_POINT('',(0.,52.121054,0.));
#694=DIRECTION('',(0.,1.,0.));
#695=DIRECTION('',(0.,0.,1.));
#696=AXIS2_PLACEMENT_3D('',#693,#694,#695);
#697=CIRCLE('',#696,3.17492378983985);
#698=CARTESIAN_POINT('',(0.,52.121054,-3.17492378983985));
#699=VERTEX_POINT('',#698);
#700=CARTESIAN_POINT('',(0.,52.121054,3.17492378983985));
#701=VERTEX_POINT('',#700);
#702=EDGE_CURVE('P1_E268',#699,#701,#697,.T.);
#703=ORIENTED_EDGE('',*,*,#702,.T.);
#704=CARTESIAN_POINT('',(0.,52.121054,2.92092378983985));
#705=DIRECTION('',(-1.,0.,0.));
#706=DIRECTION('',(0.,0.,1.));
#707=AXIS2_PLACEMENT_3D('',#704,#705,#706);
#708=CIRCLE('',#707,0.254);
#709=EDGE_CURVE('P1_E180',#701,#636,#708,.T.);
#710=ORIENTED_EDGE('',*,*,#709,.T.);
#711=ORIENTED_EDGE('',*,*,#644,.T.);
#712=ORIENTED_EDGE('',*,*,#637,.T.);
#713=ORIENTED_EDGE('',*,*,#709,.F.);
#714=CARTESIAN_POINT('',(0.,52.121054,0.));
#715=DIRECTION('',(0.,1.,0.));
#716=DIRECTION('',(0.,0.,1.));
#717=AXIS2_PLACEMENT_3D('',#714,#715,#716);
#718=CIRCLE('',#717,3.17492378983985);
#719=EDGE_CURVE('P1_E340',#701,#699,#718,.T.);
#720=ORIENTED_EDGE('',*,*,#719,.T.);
#721=EDGE_LOOP('',(#703,#710,#711,#712,#713,#720));
#722=FACE_BOUND('',#721,.T.);
#723=ADVANCED_FACE('P1_F487',(#722),#692,.T.);
#724=CARTESIAN_POINT('',(0.,51.5876539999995,0.));
#725=DIRECTION('',(0.,-1.,0.));
#726=DIRECTION('',(0.,0.,-1.));
#727=AXIS2_PLACEMENT_3D('',#724,#725,#726);
#728=CYLINDRICAL_SURFACE('',#727,3.17492378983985);
#729=CARTESIAN_POINT('',(0.,50.800253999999,0.));
#730=DIRECTION('',(0.,-1.,0.));
#731=DIRECTION('',(1.,0.,0.));
#732=AXIS2_PLACEMENT_3D('',#729,#730,#731);
#733=CIRCLE('',#732,3.17492378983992);
#734=CARTESIAN_POINT('',(0.,50.800253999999,-3.17492378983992));
#735=VERTEX_POINT('',#734);
#736=CARTESIAN_POINT('',(0.,50.800253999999,3.17492378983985));
#737=VERTEX_POINT('',#736);
#738=EDGE_CURVE('P1_E321',#735,#737,#733,.T.);
#739=ORIENTED_EDGE('',*,*,#738,.F.);
#740=CARTESIAN_POINT('',(0.,50.800253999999,0.));
#741=DIRECTION('',(0.,-1.,0.));
#742=DIRECTION('',(1.,0.,0.));
#743=AXIS2_PLACEMENT_3D('',#740,#741,#742);
#744=CIRCLE('',#743,3.17492378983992);
#745=EDGE_CURVE('P1_E317',#737,#735,#744,.T.);
#746=ORIENTED_EDGE('',*,*,#745,.F.);
#747=DIRECTION('',(0.,1.,0.));
#748=VECTOR('',#747,1.);
#749=CARTESIAN_POINT('',(0.,51.5876539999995,3.17492378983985));
#750=LINE('',#749,#748);
#751=EDGE_CURVE('P1_E336',#737,#701,#750,.T.);
#752=ORIENTED_EDGE('',*,*,#751,.T.);
#753=ORIENTED_EDGE('',*,*,#702,.F.);
#754=ORIENTED_EDGE('',*,*,#719,.F.);
#755=ORIENTED_EDGE('',*,*,#751,.F.);
#756=EDGE_LOOP('',(#739,#746,#752,#753,#754,#755));
#757=FACE_BOUND('',#756,.T.);
#758=ADVANCED_FACE('P1_F476',(#757),#728,.T.);
#759=CARTESIAN_POINT('',(0.,29.8958,0.));
#760=DIRECTION('',(0.,-1.,0.));
#761=DIRECTION('',(0.,0.,-1.));
#762=AXIS2_PLACEMENT_3D('',#759,#760,#761);
#763=TOROIDAL_SURFACE('',#762,7.1501,0.254);
#764=CARTESIAN_POINT('',(0.,29.8958,0.));
#765=DIRECTION('',(0.,1.,0.));
#766=DIRECTION('',(0.,0.,1.));
#767=AXIS2_PLACEMENT_3D('',#764,#765,#766);
#768=CIRCLE('',#767,7.4041);
#769=CARTESIAN_POINT('',(0.,29.8958,-7.4041));
#770=VERTEX_POINT('',#769);
#771=CARTESIAN_POINT('',(0.,29.8958,7.4041));
#772=VERTEX_POINT('',#771);
#773=EDGE_CURVE('P1_E137',#770,#772,#768,.T.);
#774=ORIENTED_EDGE('',*,*,#773,.T.);
#775=CARTESIAN_POINT('',(0.,29.8958,7.1501));
#776=DIRECTION('',(-1.,0.,0.));
#777=DIRECTION('',(0.,0.,1.));
#778=AXIS2_PLACEMENT_3D('',#775,#776,#777);
#779=CIRCLE('',#778,0.254);
#780=CARTESIAN_POINT('',(0.,30.1498,7.1501));
#781=VERTEX_POINT('',#780);
#782=EDGE_CURVE('P1_E133',#772,#781,#779,.T.);
#783=ORIENTED_EDGE('',*,*,#782,.T.);
#784=CARTESIAN_POINT('',(0.,30.1498,0.));
#785=DIRECTION('',(0.,-1.,0.));
#786=DIRECTION('',(0.,0.,1.));
#787=AXIS2_PLACEMENT_3D('',#784,#785,#786);
#788=CIRCLE('',#787,7.1501);
#789=CARTESIAN_POINT('',(0.,30.1498,-7.1501));
#790=VERTEX_POINT('',#789);
#791=EDGE_CURVE('P1_E138',#781,#790,#788,.T.);
#792=ORIENTED_EDGE('',*,*,#791,.T.);
#793=CARTESIAN_POINT('',(0.,30.1498,0.));
#794=DIRECTION('',(0.,-1.,0.));
#795=DIRECTION('',(0.,0.,1.));
#796=AXIS2_PLACEMENT_3D('',#793,#794,#795);
#797=CIRCLE('',#796,7.1501);
#798=EDGE_CURVE('P1_E159',#790,#781,#797,.T.);
#799=ORIENTED_EDGE('',*,*,#798,.T.);
#800=ORIENTED_EDGE('',*,*,#782,.F.);
#801=CARTESIAN_POINT('',(0.,29.8958,0.));
#802=DIRECTION('',(0.,1.,0.));
#803=DIRECTION('',(0.,0.,1.));
#804=AXIS2_PLACEMENT_3D('',#801,#802,#803);
#805=CIRCLE('',#804,7.4041);
#806=EDGE_CURVE('P1_E127',#772,#770,#805,.T.);
#807=ORIENTED_EDGE('',*,*,#806,.T.);
#808=EDGE_LOOP('',(#774,#783,#792,#799,#800,#807));
#809=FACE_BOUND('',#808,.T.);
#810=ADVANCED_FACE('P1_F716',(#809),#763,.T.);
#811=CARTESIAN_POINT('',(0.,30.1498,-7.4041));
#812=DIRECTION('',(0.,1.,0.));
#813=DIRECTION('',(1.,0.,0.));
#814=AXIS2_PLACEMENT_3D('',#811,#812,#813);
#815=PLANE('',#814);
#816=ORIENTED_EDGE('',*,*,#798,.F.);
#817=ORIENTED_EDGE('',*,*,#791,.F.);
#818=EDGE_LOOP('',(#816,#817));
#819=FACE_BOUND('',#818,.T.);
#820=CARTESIAN_POINT('',(0.,30.1498,0.));
#821=DIRECTION('',(0.,-1.,0.));
#822=DIRECTION('',(1.,0.,0.));
#823=AXIS2_PLACEMENT_3D('',#820,#821,#822);
#824=CIRCLE('',#823,4.12750000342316);
#825=CARTESIAN_POINT('',(0.,30.1498,-4.12750000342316));
#826=VERTEX_POINT('',#825);
#827=CARTESIAN_POINT('',(0.,30.1498,4.12750000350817));
#828=VERTEX_POINT('',#827);
#829=EDGE_CURVE('P1_E123',#826,#828,#824,.T.);
#830=ORIENTED_EDGE('',*,*,#829,.T.);
#831=CARTESIAN_POINT('',(0.,30.1498,0.));
#832=DIRECTION('',(0.,-1.,0.));
#833=DIRECTION('',(1.,0.,0.));
#834=AXIS2_PLACEMENT_3D('',#831,#832,#833);
#835=CIRCLE('',#834,4.12750000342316);
#836=EDGE_CURVE('P1_E128',#828,#826,#835,.T.);
#837=ORIENTED_EDGE('',*,*,#836,.T.);
#838=EDGE_LOOP('',(#830,#837));
#839=FACE_BOUND('',#838,.T.);
#840=ADVANCED_FACE('P1_F712',(#819,#839),#815,.T.);
#841=CARTESIAN_POINT('',(0.,22.6949,0.));
#842=DIRECTION('',(0.,-1.,0.));
#843=DIRECTION('',(0.,0.,-1.));
#844=AXIS2_PLACEMENT_3D('',#841,#842,#843);
#845=CYLINDRICAL_SURFACE('',#844,7.4041);
#846=DIRECTION('',(0.,1.,0.));
#847=VECTOR('',#846,1.);
#848=CARTESIAN_POINT('',(0.,22.6949,7.4041));
#849=LINE('',#848,#847);
#850=CARTESIAN_POINT('',(0.,15.24,7.4041));
#851=VERTEX_POINT('',#850);
#852=CARTESIAN_POINT('',(0.,25.3999996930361,7.4041));
#853=VERTEX_POINT('',#852);
#854=EDGE_CURVE('P1_E132',#851,#853,#849,.T.);
#855=ORIENTED_EDGE('',*,*,#854,.T.);
#856=ORIENTED_EDGE('',*,*,#854,.F.);
#857=CARTESIAN_POINT('',(0.,15.24,0.));
#858=DIRECTION('',(0.,-1.,0.));
#859=DIRECTION('',(1.,0.,0.));
#860=AXIS2_PLACEMENT_3D('',#857,#858,#859);
#861=CIRCLE('',#860,7.4041);
#862=CARTESIAN_POINT('',(0.,15.24,-7.4041));
#863=VERTEX_POINT('',#862);
#864=EDGE_CURVE('P1_E188',#863,#851,#861,.T.);
#865=ORIENTED_EDGE('',*,*,#864,.F.);
#866=CARTESIAN_POINT('',(0.,15.24,0.));
#867=DIRECTION('',(0.,-1.,0.));
#868=DIRECTION('',(1.,0.,0.));
#869=AXIS2_PLACEMENT_3D('',#866,#867,#868);
#870=CIRCLE('',#869,7.4041);
#871=EDGE_CURVE('P1_E193',#851,#863,#870,.T.);
#872=ORIENTED_EDGE('',*,*,#871,.F.);
#873=EDGE_LOOP('',(#855,#856,#865,#872));
#874=FACE_BOUND('',#873,.T.);
#875=DIRECTION('',(0.,1.,0.));
#876=VECTOR('',#875,1.);
#877=CARTESIAN_POINT('',(0.,22.6949,7.4041));
#878=LINE('',#877,#876);
#879=CARTESIAN_POINT('',(0.,28.1939996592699,7.4041));
#880=VERTEX_POINT('',#879);
#881=EDGE_CURVE('P1_E151',#880,#772,#878,.T.);
#882=ORIENTED_EDGE('',*,*,#881,.F.);
#883=ORIENTED_EDGE('',*,*,#881,.T.);
#884=ORIENTED_EDGE('',*,*,#773,.F.);
#885=ORIENTED_EDGE('',*,*,#806,.F.);
#886=EDGE_LOOP('',(#882,#883,#884,#885));
#887=FACE_BOUND('',#886,.T.);
#888=ADVANCED_FACE('P1_F691',(#874,#887),#845,.T.);
#889=CARTESIAN_POINT('',(0.,0.3937,0.));
#890=DIRECTION('',(0.,-1.,0.));
#891=DIRECTION('',(0.,0.,1.));
#892=AXIS2_PLACEMENT_3D('',#889,#890,#891);
#893=CONICAL_SURFACE('',#892,5.1689,0.78539816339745);
#894=CARTESIAN_POINT('',(0.,0.7874,0.));
#895=DIRECTION('',(0.,1.,0.));
#896=DIRECTION('',(0.,0.,1.));
#897=AXIS2_PLACEMENT_3D('',#894,#895,#896);
#898=CIRCLE('',#897,4.7752);
#899=CARTESIAN_POINT('',(0.,0.7874,-4.7752));
#900=VERTEX_POINT('',#899);
#901=CARTESIAN_POINT('',(0.,0.7874,4.7752));
#902=VERTEX_POINT('',#901);
#903=EDGE_CURVE('P1_E155',#900,#902,#898,.T.);
#904=ORIENTED_EDGE('',*,*,#903,.T.);
#905=CARTESIAN_POINT('',(0.,0.7874,0.));
#906=DIRECTION('',(0.,1.,0.));
#907=DIRECTION('',(0.,0.,1.));
#908=AXIS2_PLACEMENT_3D('',#905,#906,#907);
#909=CIRCLE('',#908,4.7752);
#910=EDGE_CURVE('P1_E302',#902,#900,#909,.T.);
#911=ORIENTED_EDGE('',*,*,#910,.T.);
#912=DIRECTION('',(0.,-0.707106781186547,-0.707106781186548));
#913=VECTOR('',#912,1.);
#914=CARTESIAN_POINT('',(0.,0.3937,-5.1689));
#915=LINE('',#914,#913);
#916=CARTESIAN_POINT('',(0.,0.,-5.5626));
#917=VERTEX_POINT('',#916);
#918=EDGE_CURVE('P1_E298',#900,#917,#915,.T.);
#919=ORIENTED_EDGE('',*,*,#918,.T.);
#920=CARTESIAN_POINT('',(0.,0.,0.));
#921=DIRECTION('',(0.,-1.,0.));
#922=DIRECTION('',(0.,0.,1.));
#923=AXIS2_PLACEMENT_3D('',#920,#921,#922);
#924=CIRCLE('',#923,5.5626);
#925=EDGE_CURVE('P1_E143',#917,#917,#924,.T.);
#926=ORIENTED_EDGE('',*,*,#925,.T.);
#927=ORIENTED_EDGE('',*,*,#918,.F.);
#928=EDGE_LOOP('',(#904,#911,#919,#926,#927));
#929=FACE_BOUND('',#928,.T.);
#930=ADVANCED_FACE('P1_F688',(#929),#893,.F.);
#931=CARTESIAN_POINT('',(0.,0.,-4.7752));
#932=DIRECTION('',(0.,-1.,0.));
#933=DIRECTION('',(0.,0.,-1.));
#934=AXIS2_PLACEMENT_3D('',#931,#932,#933);
#935=PLANE('',#934);
#936=CARTESIAN_POINT('',(0.,0.,0.));
#937=DIRECTION('',(0.,-1.,0.));
#938=DIRECTION('',(1.,0.,0.));
#939=AXIS2_PLACEMENT_3D('',#936,#937,#938);
#940=CIRCLE('',#939,6.35);
#941=CARTESIAN_POINT('',(0.,0.,-6.35));
#942=VERTEX_POINT('',#941);
#943=CARTESIAN_POINT('',(0.,0.,6.35));
#944=VERTEX_POINT('',#943);
#945=EDGE_CURVE('P1_E139',#942,#944,#940,.T.);
#946=ORIENTED_EDGE('',*,*,#945,.T.);
#947=CARTESIAN_POINT('',(0.,0.,0.));
#948=DIRECTION('',(0.,-1.,0.));
#949=DIRECTION('',(1.,0.,0.));
#950=AXIS2_PLACEMENT_3D('',#947,#948,#949);
#951=CIRCLE('',#950,6.35);
#952=EDGE_CURVE('P1_E144',#944,#942,#951,.T.);
#953=ORIENTED_EDGE('',*,*,#952,.T.);
#954=EDGE_LOOP('',(#946,#953));
#955=FACE_BOUND('',#954,.T.);
#956=ORIENTED_EDGE('',*,*,#925,.F.);
#957=EDGE_LOOP('',(#956));
#958=FACE_BOUND('',#957,.T.);
#959=ADVANCED_FACE('P1_F690',(#955,#958),#935,.T.);
#960=CARTESIAN_POINT('',(0.,4.0595423,0.));
#961=DIRECTION('',(0.,-1.,0.));
#962=DIRECTION('',(0.,0.,-1.));
#963=AXIS2_PLACEMENT_3D('',#960,#961,#962);
#964=CYLINDRICAL_SURFACE('',#963,4.7752);
#965=ORIENTED_EDGE('',*,*,#903,.F.);
#966=ORIENTED_EDGE('',*,*,#910,.F.);
#967=DIRECTION('',(0.,1.,0.));
#968=VECTOR('',#967,1.);
#969=CARTESIAN_POINT('',(0.,4.0595423,4.7752));
#970=LINE('',#969,#968);
#971=CARTESIAN_POINT('',(0.,8.1190846,4.7752));
#972=VERTEX_POINT('',#971);
#973=EDGE_CURVE('P1_E164',#902,#972,#970,.T.);
#974=ORIENTED_EDGE('',*,*,#973,.T.);
#975=CARTESIAN_POINT('',(0.,8.1190846,0.));
#976=DIRECTION('',(0.,-1.,0.));
#977=DIRECTION('',(1.,0.,0.));
#978=AXIS2_PLACEMENT_3D('',#975,#976,#977);
#979=CIRCLE('',#978,4.7752);
#980=CARTESIAN_POINT('',(0.,8.1190846,-4.7752));
#981=VERTEX_POINT('',#980);
#982=EDGE_CURVE('P1_E241',#981,#972,#979,.T.);
#983=ORIENTED_EDGE('',*,*,#982,.F.);
#984=CARTESIAN_POINT('',(0.,8.1190846,0.));
#985=DIRECTION('',(0.,-1.,0.));
#986=DIRECTION('',(1.,0.,0.));
#987=AXIS2_PLACEMENT_3D('',#984,#985,#986);
#988=CIRCLE('',#987,4.7752);
#989=EDGE_CURVE('P1_E198',#972,#981,#988,.T.);
#990=ORIENTED_EDGE('',*,*,#989,.F.);
#991=ORIENTED_EDGE('',*,*,#973,.F.);
#992=EDGE_LOOP('',(#965,#966,#974,#983,#990,#991));
#993=FACE_BOUND('',#992,.T.);
#994=ADVANCED_FACE('P1_F735',(#993),#964,.F.);
#995=CARTESIAN_POINT('',(0.,12.8524,-3.3782));
#996=DIRECTION('',(0.,-1.,0.));
#997=DIRECTION('',(0.,0.,-1.));
#998=AXIS2_PLACEMENT_3D('',#995,#996,#997);
#999=PLANE('',#998);
#1000=CARTESIAN_POINT('',(0.,12.8524,0.));
#1001=DIRECTION('',(0.,-1.,0.));
#1002=DIRECTION('',(1.,0.,0.));
#1003=AXIS2_PLACEMENT_3D('',#1000,#1001,#1002);
#1004=CIRCLE('',#1003,5.0546);
#1005=CARTESIAN_POINT('',(0.,12.8524,-5.0546));
#1006=VERTEX_POINT('',#1005);
#1007=CARTESIAN_POINT('',(0.,12.8524,5.0546));
#1008=VERTEX_POINT('',#1007);
#1009=EDGE_CURVE('P1_E160',#1006,#1008,#1004,.T.);
#1010=ORIENTED_EDGE('',*,*,#1009,.T.);
#1011=CARTESIAN_POINT('',(0.,12.8524,0.));
#1012=DIRECTION('',(0.,-1.,0.));
#1013=DIRECTION('',(1.,0.,0.));
#1014=AXIS2_PLACEMENT_3D('',#1011,#1012,#1013);
#1015=CIRCLE('',#1014,5.0546);
#1016=EDGE_CURVE('P1_E149',#1008,#1006,#1015,.T.);
#1017=ORIENTED_EDGE('',*,*,#1016,.T.);
#1018=EDGE_LOOP('',(#1010,#1017));
#1019=FACE_BOUND('',#1018,.T.);
#1020=CARTESIAN_POINT('',(0.,12.8524,0.));
#1021=DIRECTION('',(0.,-1.,0.));
#1022=DIRECTION('',(1.,0.,0.));
#1023=AXIS2_PLACEMENT_3D('',#1020,#1021,#1022);
#1024=CIRCLE('',#1023,3.3782);
#1025=CARTESIAN_POINT('',(0.,12.8524,-3.3782));
#1026=VERTEX_POINT('',#1025);
#1027=CARTESIAN_POINT('',(0.,12.8524,3.3782));
#1028=VERTEX_POINT('',#1027);
#1029=EDGE_CURVE('P1_E145',#1026,#1028,#1024,.T.);
#1030=ORIENTED_EDGE('',*,*,#1029,.F.);
#1031=CARTESIAN_POINT('',(0.,12.8524,0.));
#1032=DIRECTION('',(0.,-1.,0.));
#1033=DIRECTION('',(1.,0.,0.));
#1034=AXIS2_PLACEMENT_3D('',#1031,#1032,#1033);
#1035=CIRCLE('',#1034,3.3782);
#1036=EDGE_CURVE('P1_E209',#1028,#1026,#1035,.T.);
#1037=ORIENTED_EDGE('',*,*,#1036,.F.);
#1038=EDGE_LOOP('',(#1030,#1037));
#1039=FACE_BOUND('',#1038,.T.);
#1040=ADVANCED_FACE('P1_F651',(#1019,#1039),#999,.T.);
#1041=CARTESIAN_POINT('',(0.,19.9136,0.));
#1042=DIRECTION('',(0.,-1.,0.));
#1043=DIRECTION('',(0.,0.,-1.));
#1044=AXIS2_PLACEMENT_3D('',#1041,#1042,#1043);
#1045=CYLINDRICAL_SURFACE('',#1044,3.3782);
#1046=ORIENTED_EDGE('',*,*,#1029,.T.);
#1047=DIRECTION('',(0.,1.,0.));
#1048=VECTOR('',#1047,1.);
#1049=CARTESIAN_POINT('',(0.,19.9136,3.3782));
#1050=LINE('',#1049,#1048);
#1051=CARTESIAN_POINT('',(0.,26.9748,3.3782));
#1052=VERTEX_POINT('',#1051);
#1053=EDGE_CURVE('P1_E150',#1028,#1052,#1050,.T.);
#1054=ORIENTED_EDGE('',*,*,#1053,.T.);
#1055=CARTESIAN_POINT('',(0.,26.9748,0.));
#1056=DIRECTION('',(0.,-1.,0.));
#1057=DIRECTION('',(1.,0.,0.));
#1058=AXIS2_PLACEMENT_3D('',#1055,#1056,#1057);
#1059=CIRCLE('',#1058,3.3782);
#1060=CARTESIAN_POINT('',(0.,26.9748,-3.3782));
#1061=VERTEX_POINT('',#1060);
#1062=EDGE_CURVE('P1_E186',#1061,#1052,#1059,.T.);
#1063=ORIENTED_EDGE('',*,*,#1062,.F.);
#1064=CARTESIAN_POINT('',(0.,26.9748,0.));
#1065=DIRECTION('',(0.,-1.,0.));
#1066=DIRECTION('',(1.,0.,0.));
#1067=AXIS2_PLACEMENT_3D('',#1064,#1065,#1066);
#1068=CIRCLE('',#1067,3.3782);
#1069=EDGE_CURVE('P1_E182',#1052,#1061,#1068,.T.);
#1070=ORIENTED_EDGE('',*,*,#1069,.F.);
#1071=ORIENTED_EDGE('',*,*,#1053,.F.);
#1072=ORIENTED_EDGE('',*,*,#1036,.T.);
#1073=EDGE_LOOP('',(#1046,#1054,#1063,#1070,#1071,#1072));
#1074=FACE_BOUND('',#1073,.T.);
#1075=ADVANCED_FACE('P1_F642',(#1074),#1045,.F.);
#1076=CARTESIAN_POINT('',(0.,26.9748,-2.5780999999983));
#1077=DIRECTION('',(0.,-1.,0.));
#1078=DIRECTION('',(0.,0.,-1.));
#1079=AXIS2_PLACEMENT_3D('',#1076,#1077,#1078);
#1080=PLANE('',#1079);
#1081=ORIENTED_EDGE('',*,*,#1062,.T.);
#1082=ORIENTED_EDGE('',*,*,#1069,.T.);
#1083=EDGE_LOOP('',(#1081,#1082));
#1084=FACE_BOUND('',#1083,.T.);
#1085=ORIENTED_EDGE('',*,*,#667,.F.);
#1086=ORIENTED_EDGE('',*,*,#683,.F.);
#1087=EDGE_LOOP('',(#1085,#1086));
#1088=FACE_BOUND('',#1087,.T.);
#1089=ADVANCED_FACE('P1_F640',(#1084,#1088),#1080,.T.);
#1090=CARTESIAN_POINT('',(0.,49.3016539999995,0.));
#1091=DIRECTION('',(0.,-1.,0.));
#1092=DIRECTION('',(0.,0.,-1.));
#1093=AXIS2_PLACEMENT_3D('',#1090,#1091,#1092);
#1094=CONICAL_SURFACE('',#1093,3.72036958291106,0.349065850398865);
#1095=CARTESIAN_POINT('',(0.,47.803054,0.));
#1096=DIRECTION('',(0.,-1.,0.));
#1097=DIRECTION('',(1.,0.,0.));
#1098=AXIS2_PLACEMENT_3D('',#1095,#1096,#1097);
#1099=CIRCLE('',#1098,4.26581537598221);
#1100=CARTESIAN_POINT('',(0.,47.803054,-4.26581537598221));
#1101=VERTEX_POINT('',#1100);
#1102=CARTESIAN_POINT('',(0.,47.803054,4.26581537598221));
#1103=VERTEX_POINT('',#1102);
#1104=EDGE_CURVE('P1_E217',#1101,#1103,#1099,.T.);
#1105=ORIENTED_EDGE('',*,*,#1104,.F.);
#1106=CARTESIAN_POINT('',(0.,47.803054,0.));
#1107=DIRECTION('',(0.,-1.,0.));
#1108=DIRECTION('',(1.,0.,0.));
#1109=AXIS2_PLACEMENT_3D('',#1106,#1107,#1108);
#1110=CIRCLE('',#1109,4.26581537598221);
#1111=EDGE_CURVE('P1_E364',#1103,#1101,#1110,.T.);
#1112=ORIENTED_EDGE('',*,*,#1111,.F.);
#1113=DIRECTION('',(0.,0.939692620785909,-0.342020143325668));
#1114=VECTOR('',#1113,1.);
#1115=CARTESIAN_POINT('',(0.,49.3016539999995,3.72036958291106));
#1116=LINE('',#1115,#1114);
#1117=EDGE_CURVE('P1_E187',#1103,#737,#1116,.T.);
#1118=ORIENTED_EDGE('',*,*,#1117,.T.);
#1119=ORIENTED_EDGE('',*,*,#745,.T.);
#1120=ORIENTED_EDGE('',*,*,#738,.T.);
#1121=ORIENTED_EDGE('',*,*,#1117,.F.);
#1122=EDGE_LOOP('',(#1105,#1112,#1118,#1119,#1120,#1121));
#1123=FACE_BOUND('',#1122,.T.);
#1124=ADVANCED_FACE('P1_F467',(#1123),#1094,.T.);
#1125=CARTESIAN_POINT('',(0.,47.549054,0.));
#1126=DIRECTION('',(0.,-1.,0.));
#1127=DIRECTION('',(0.,0.,-1.));
#1128=AXIS2_PLACEMENT_3D('',#1125,#1126,#1127);
#1129=CYLINDRICAL_SURFACE('',#1128,4.26581537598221);
#1130=CARTESIAN_POINT('',(0.,47.295054,0.));
#1131=DIRECTION('',(0.,-1.,0.));
#1132=DIRECTION('',(1.,0.,0.));
#1133=AXIS2_PLACEMENT_3D('',#1130,#1131,#1132);
#1134=CIRCLE('',#1133,4.26581537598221);
#1135=CARTESIAN_POINT('',(0.,47.295054,-4.26581537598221));
#1136=VERTEX_POINT('',#1135);
#1137=CARTESIAN_POINT('',(0.,47.295054,4.26581537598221));
#1138=VERTEX_POINT('',#1137);
#1139=EDGE_CURVE('P1_E214',#1136,#1138,#1134,.T.);
#1140=ORIENTED_EDGE('',*,*,#1139,.F.);
#1141=CARTESIAN_POINT('',(0.,47.295054,0.));
#1142=DIRECTION('',(0.,-1.,0.));
#1143=DIRECTION('',(1.,0.,0.));
#1144=AXIS2_PLACEMENT_3D('',#1141,#1142,#1143);
#1145=CIRCLE('',#1144,4.26581537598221);
#1146=EDGE_CURVE('P1_E218',#1138,#1136,#1145,.T.);
#1147=ORIENTED_EDGE('',*,*,#1146,.F.);
#1148=DIRECTION('',(0.,1.,0.));
#1149=VECTOR('',#1148,1.);
#1150=CARTESIAN_POINT('',(0.,47.549054,4.26581537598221));
#1151=LINE('',#1150,#1149);
#1152=EDGE_CURVE('P1_E335',#1138,#1103,#1151,.T.);
#1153=ORIENTED_EDGE('',*,*,#1152,.T.);
#1154=ORIENTED_EDGE('',*,*,#1111,.T.);
#1155=ORIENTED_EDGE('',*,*,#1104,.T.);
#1156=ORIENTED_EDGE('',*,*,#1152,.F.);
#1157=EDGE_LOOP('',(#1140,#1147,#1153,#1154,#1155,#1156));
#1158=FACE_BOUND('',#1157,.T.);
#1159=ADVANCED_FACE('P1_F458',(#1158),#1129,.T.);
#1160=CARTESIAN_POINT('',(0.,47.295054,-3.302));
#1161=DIRECTION('',(0.,-1.,0.));
#1162=DIRECTION('',(0.,0.,-1.));
#1163=AXIS2_PLACEMENT_3D('',#1160,#1161,#1162);
#1164=PLANE('',#1163);
#1165=ORIENTED_EDGE('',*,*,#1139,.T.);
#1166=ORIENTED_EDGE('',*,*,#1146,.T.);
#1167=EDGE_LOOP('',(#1165,#1166));
#1168=FACE_BOUND('',#1167,.T.);
#1169=CARTESIAN_POINT('',(0.,47.295054,0.));
#1170=DIRECTION('',(0.,-1.,0.));
#1171=DIRECTION('',(1.,0.,0.));
#1172=AXIS2_PLACEMENT_3D('',#1169,#1170,#1171);
#1173=CIRCLE('',#1172,3.302);
#1174=CARTESIAN_POINT('',(0.,47.295054,-3.302));
#1175=VERTEX_POINT('',#1174);
#1176=CARTESIAN_POINT('',(0.,47.295054,3.302));
#1177=VERTEX_POINT('',#1176);
#1178=EDGE_CURVE('P1_E230',#1175,#1177,#1173,.T.);
#1179=ORIENTED_EDGE('',*,*,#1178,.F.);
#1180=CARTESIAN_POINT('',(0.,47.295054,0.));
#1181=DIRECTION('',(0.,-1.,0.));
#1182=DIRECTION('',(1.,0.,0.));
#1183=AXIS2_PLACEMENT_3D('',#1180,#1181,#1182);
#1184=CIRCLE('',#1183,3.302);
#1185=EDGE_CURVE('P1_E344',#1177,#1175,#1184,.T.);
#1186=ORIENTED_EDGE('',*,*,#1185,.F.);
#1187=EDGE_LOOP('',(#1179,#1186));
#1188=FACE_BOUND('',#1187,.T.);
#1189=ADVANCED_FACE('P1_F717',(#1168,#1188),#1164,.T.);
#1190=CARTESIAN_POINT('',(0.,44.8090844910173,0.));
#1191=DIRECTION('',(0.,-1.,0.));
#1192=DIRECTION('',(0.,0.,-1.));
#1193=AXIS2_PLACEMENT_3D('',#1190,#1191,#1192);
#1194=CYLINDRICAL_SURFACE('',#1193,3.302);
#1195=CARTESIAN_POINT('',(0.,42.3231149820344,0.));
#1196=DIRECTION('',(0.,-1.,0.));
#1197=DIRECTION('',(1.,0.,0.));
#1198=AXIS2_PLACEMENT_3D('',#1195,#1196,#1197);
#1199=CIRCLE('',#1198,3.302);
#1200=CARTESIAN_POINT('',(0.,42.3231149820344,-3.302));
#1201=VERTEX_POINT('',#1200);
#1202=CARTESIAN_POINT('',(0.,42.3231149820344,3.302));
#1203=VERTEX_POINT('',#1202);
#1204=EDGE_CURVE('P1_E118',#1201,#1203,#1199,.T.);
#1205=ORIENTED_EDGE('',*,*,#1204,.F.);
#1206=CARTESIAN_POINT('',(0.,42.3231149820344,0.));
#1207=DIRECTION('',(0.,-1.,0.));
#1208=DIRECTION('',(1.,0.,0.));
#1209=AXIS2_PLACEMENT_3D('',#1206,#1207,#1208);
#1210=CIRCLE('',#1209,3.302);
#1211=EDGE_CURVE('P1_E121',#1203,#1201,#1210,.T.);
#1212=ORIENTED_EDGE('',*,*,#1211,.F.);
#1213=DIRECTION('',(0.,1.,0.));
#1214=VECTOR('',#1213,1.);
#1215=CARTESIAN_POINT('',(0.,44.8090844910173,3.302));
#1216=LINE('',#1215,#1214);
#1217=EDGE_CURVE('P1_E297',#1203,#1177,#1216,.T.);
#1218=ORIENTED_EDGE('',*,*,#1217,.T.);
#1219=ORIENTED_EDGE('',*,*,#1185,.T.);
#1220=ORIENTED_EDGE('',*,*,#1178,.T.);
#1221=ORIENTED_EDGE('',*,*,#1217,.F.);
#1222=EDGE_LOOP('',(#1205,#1212,#1218,#1219,#1220,#1221));
#1223=FACE_BOUND('',#1222,.T.);
#1224=ADVANCED_FACE('P1_F698',(#1223),#1194,.T.);
#1225=CARTESIAN_POINT('',(0.,40.9990844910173,0.));
#1226=DIRECTION('',(0.,-1.,0.));
#1227=DIRECTION('',(0.,0.,-1.));
#1228=AXIS2_PLACEMENT_3D('',#1225,#1226,#1227);
#1229=CONICAL_SURFACE('',#1228,3.78390768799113,0.349065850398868);
#1230=CARTESIAN_POINT('',(0.,39.675054,0.));
#1231=DIRECTION('',(0.,-1.,0.));
#1232=DIRECTION('',(1.,0.,0.));
#1233=AXIS2_PLACEMENT_3D('',#1230,#1231,#1232);
#1234=CIRCLE('',#1233,4.26581537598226);
#1235=CARTESIAN_POINT('',(0.,39.675054,-4.26581537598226));
#1236=VERTEX_POINT('',#1235);
#1237=CARTESIAN_POINT('',(0.,39.675054,4.26581537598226));
#1238=VERTEX_POINT('',#1237);
#1239=EDGE_CURVE('P1_E277',#1236,#1238,#1234,.T.);
#1240=ORIENTED_EDGE('',*,*,#1239,.F.);
#1241=CARTESIAN_POINT('',(0.,39.675054,0.));
#1242=DIRECTION('',(0.,-1.,0.));
#1243=DIRECTION('',(1.,0.,0.));
#1244=AXIS2_PLACEMENT_3D('',#1241,#1242,#1243);
#1245=CIRCLE('',#1244,4.26581537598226);
#1246=EDGE_CURVE('P1_E280',#1238,#1236,#1245,.T.);
#1247=ORIENTED_EDGE('',*,*,#1246,.F.);
#1248=DIRECTION('',(0.,0.939692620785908,-0.34202014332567));
#1249=VECTOR('',#1248,1.);
#1250=CARTESIAN_POINT('',(0.,40.9990844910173,3.78390768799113));
#1251=LINE('',#1250,#1249);
#1252=EDGE_CURVE('P1_E226',#1238,#1203,#1251,.T.);
#1253=ORIENTED_EDGE('',*,*,#1252,.T.);
#1254=ORIENTED_EDGE('',*,*,#1211,.T.);
#1255=ORIENTED_EDGE('',*,*,#1204,.T.);
#1256=ORIENTED_EDGE('',*,*,#1252,.F.);
#1257=EDGE_LOOP('',(#1240,#1247,#1253,#1254,#1255,#1256));
#1258=FACE_BOUND('',#1257,.T.);
#1259=ADVANCED_FACE('P1_F686',(#1258),#1229,.T.);
#1260=CARTESIAN_POINT('',(0.,39.421054,0.));
#1261=DIRECTION('',(0.,-1.,0.));
#1262=DIRECTION('',(0.,0.,-1.));
#1263=AXIS2_PLACEMENT_3D('',#1260,#1261,#1262);
#1264=CYLINDRICAL_SURFACE('',#1263,4.26581537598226);
#1265=CARTESIAN_POINT('',(0.,39.167054,0.));
#1266=DIRECTION('',(0.,-1.,0.));
#1267=DIRECTION('',(1.,0.,0.));
#1268=AXIS2_PLACEMENT_3D('',#1265,#1266,#1267);
#1269=CIRCLE('',#1268,4.26581537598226);
#1270=CARTESIAN_POINT('',(0.,39.167054,-4.26581537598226));
#1271=VERTEX_POINT('',#1270);
#1272=CARTESIAN_POINT('',(0.,39.167054,4.26581537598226));
#1273=VERTEX_POINT('',#1272);
#1274=EDGE_CURVE('P1_E235',#1271,#1273,#1269,.T.);
#1275=ORIENTED_EDGE('',*,*,#1274,.F.);
#1276=CARTESIAN_POINT('',(0.,39.167054,0.));
#1277=DIRECTION('',(0.,-1.,0.));
#1278=DIRECTION('',(1.,0.,0.));
#1279=AXIS2_PLACEMENT_3D('',#1276,#1277,#1278);
#1280=CIRCLE('',#1279,4.26581537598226);
#1281=EDGE_CURVE('P1_E231',#1273,#1271,#1280,.T.);
#1282=ORIENTED_EDGE('',*,*,#1281,.F.);
#1283=DIRECTION('',(0.,1.,0.));
#1284=VECTOR('',#1283,1.);
#1285=CARTESIAN_POINT('',(0.,39.421054,4.26581537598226));
#1286=LINE('',#1285,#1284);
#1287=EDGE_CURVE('P1_E122',#1273,#1238,#1286,.T.);
#1288=ORIENTED_EDGE('',*,*,#1287,.T.);
#1289=ORIENTED_EDGE('',*,*,#1246,.T.);
#1290=ORIENTED_EDGE('',*,*,#1239,.T.);
#1291=ORIENTED_EDGE('',*,*,#1287,.F.);
#1292=EDGE_LOOP('',(#1275,#1282,#1288,#1289,#1290,#1291));
#1293=FACE_BOUND('',#1292,.T.);
#1294=ADVANCED_FACE('P1_F682',(#1293),#1264,.T.);
#1295=CARTESIAN_POINT('',(0.,39.167054,-3.302));
#1296=DIRECTION('',(0.,-1.,0.));
#1297=DIRECTION('',(0.,0.,-1.));
#1298=AXIS2_PLACEMENT_3D('',#1295,#1296,#1297);
#1299=PLANE('',#1298);
#1300=ORIENTED_EDGE('',*,*,#1274,.T.);
#1301=ORIENTED_EDGE('',*,*,#1281,.T.);
#1302=EDGE_LOOP('',(#1300,#1301));
#1303=FACE_BOUND('',#1302,.T.);
#1304=CARTESIAN_POINT('',(0.,39.167054,0.));
#1305=DIRECTION('',(0.,-1.,0.));
#1306=DIRECTION('',(1.,0.,0.));
#1307=AXIS2_PLACEMENT_3D('',#1304,#1305,#1306);
#1308=CIRCLE('',#1307,3.302);
#1309=CARTESIAN_POINT('',(0.,39.167054,-3.302));
#1310=VERTEX_POINT('',#1309);
#1311=CARTESIAN_POINT('',(0.,39.167054,3.302));
#1312=VERTEX_POINT('',#1311);
#1313=EDGE_CURVE('P1_E116',#1310,#1312,#1308,.T.);
#1314=ORIENTED_EDGE('',*,*,#1313,.F.);
#1315=CARTESIAN_POINT('',(0.,39.167054,0.));
#1316=DIRECTION('',(0.,-1.,0.));
#1317=DIRECTION('',(1.,0.,0.));
#1318=AXIS2_PLACEMENT_3D('',#1315,#1316,#1317);
#1319=CIRCLE('',#1318,3.302);
#1320=EDGE_CURVE('P1_E254',#1312,#1310,#1319,.T.);
#1321=ORIENTED_EDGE('',*,*,#1320,.F.);
#1322=EDGE_LOOP('',(#1314,#1321));
#1323=FACE_BOUND('',#1322,.T.);
#1324=ADVANCED_FACE('P1_F685',(#1303,#1323),#1299,.T.);
#1325=CARTESIAN_POINT('',(0.,37.643054,0.));
#1326=DIRECTION('',(0.,-1.,0.));
#1327=DIRECTION('',(0.,0.,-1.));
#1328=AXIS2_PLACEMENT_3D('',#1325,#1326,#1327);
#1329=CYLINDRICAL_SURFACE('',#1328,3.302);
#1330=CARTESIAN_POINT('',(0.,36.119054,0.));
#1331=DIRECTION('',(0.,-1.,0.));
#1332=DIRECTION('',(1.,0.,0.));
#1333=AXIS2_PLACEMENT_3D('',#1330,#1331,#1332);
#1334=CIRCLE('',#1333,3.302);
#1335=CARTESIAN_POINT('',(0.,36.119054,-3.302));
#1336=VERTEX_POINT('',#1335);
#1337=CARTESIAN_POINT('',(0.,36.119054,3.302));
#1338=VERTEX_POINT('',#1337);
#1339=EDGE_CURVE('P1_E246',#1336,#1338,#1334,.T.);
#1340=ORIENTED_EDGE('',*,*,#1339,.F.);
#1341=CARTESIAN_POINT('',(0.,36.119054,0.));
#1342=DIRECTION('',(0.,-1.,0.));
#1343=DIRECTION('',(1.,0.,0.));
#1344=AXIS2_PLACEMENT_3D('',#1341,#1342,#1343);
#1345=CIRCLE('',#1344,3.302);
#1346=EDGE_CURVE('P1_E169',#1338,#1336,#1345,.T.);
#1347=ORIENTED_EDGE('',*,*,#1346,.F.);
#1348=DIRECTION('',(0.,1.,0.));
#1349=VECTOR('',#1348,1.);
#1350=CARTESIAN_POINT('',(0.,37.643054,3.302));
#1351=LINE('',#1350,#1349);
#1352=EDGE_CURVE('P1_E236',#1338,#1312,#1351,.T.);
#1353=ORIENTED_EDGE('',*,*,#1352,.T.);
#1354=ORIENTED_EDGE('',*,*,#1320,.T.);
#1355=ORIENTED_EDGE('',*,*,#1313,.T.);
#1356=ORIENTED_EDGE('',*,*,#1352,.F.);
#1357=EDGE_LOOP('',(#1340,#1347,#1353,#1354,#1355,#1356));
#1358=FACE_BOUND('',#1357,.T.);
#1359=ADVANCED_FACE('P1_F702',(#1358),#1329,.T.);
#1360=CARTESIAN_POINT('',(0.,34.3663250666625,0.));
#1361=DIRECTION('',(0.,-1.,0.));
#1362=DIRECTION('',(0.,0.,-1.));
#1363=AXIS2_PLACEMENT_3D('',#1360,#1361,#1362);
#1364=CONICAL_SURFACE('',#1363,3.90528823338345,0.331497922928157);
#1365=CARTESIAN_POINT('',(0.,32.6135961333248,0.));
#1366=DIRECTION('',(0.,-1.,0.));
#1367=DIRECTION('',(1.,0.,0.));
#1368=AXIS2_PLACEMENT_3D('',#1365,#1366,#1367);
#1369=CIRCLE('',#1368,4.50857646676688);
#1370=CARTESIAN_POINT('',(0.,32.6135961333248,-4.50857646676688));
#1371=VERTEX_POINT('',#1370);
#1372=CARTESIAN_POINT('',(0.,32.6135961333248,4.50857646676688));
#1373=VERTEX_POINT('',#1372);
#1374=EDGE_CURVE('P1_E269',#1371,#1373,#1369,.T.);
#1375=ORIENTED_EDGE('',*,*,#1374,.F.);
#1376=CARTESIAN_POINT('',(0.,32.6135961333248,0.));
#1377=DIRECTION('',(0.,-1.,0.));
#1378=DIRECTION('',(1.,0.,0.));
#1379=AXIS2_PLACEMENT_3D('',#1376,#1377,#1378);
#1380=CIRCLE('',#1379,4.50857646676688);
#1381=EDGE_CURVE('P1_E247',#1373,#1371,#1380,.T.);
#1382=ORIENTED_EDGE('',*,*,#1381,.F.);
#1383=DIRECTION('',(0.,0.945555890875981,-0.325459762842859));
#1384=VECTOR('',#1383,1.);
#1385=CARTESIAN_POINT('',(0.,34.3663250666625,3.90528823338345));
#1386=LINE('',#1385,#1384);
#1387=EDGE_CURVE('P1_E165',#1373,#1338,#1386,.T.);
#1388=ORIENTED_EDGE('',*,*,#1387,.T.);
#1389=ORIENTED_EDGE('',*,*,#1346,.T.);
#1390=ORIENTED_EDGE('',*,*,#1339,.T.);
#1391=ORIENTED_EDGE('',*,*,#1387,.F.);
#1392=EDGE_LOOP('',(#1375,#1382,#1388,#1389,#1390,#1391));
#1393=FACE_BOUND('',#1392,.T.);
#1394=ADVANCED_FACE('P1_F810',(#1393),#1364,.T.);
#1395=CARTESIAN_POINT('',(0.,32.1690961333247,0.));
#1396=DIRECTION('',(0.,-1.,0.));
#1397=DIRECTION('',(0.,0.,-1.));
#1398=AXIS2_PLACEMENT_3D('',#1395,#1396,#1397);
#1399=CYLINDRICAL_SURFACE('',#1398,4.5085764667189);
#1400=CARTESIAN_POINT('',(0.,31.7245961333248,0.));
#1401=DIRECTION('',(0.,-1.,0.));
#1402=DIRECTION('',(1.,0.,0.));
#1403=AXIS2_PLACEMENT_3D('',#1400,#1401,#1402);
#1404=CIRCLE('',#1403,4.50857646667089);
#1405=CARTESIAN_POINT('',(0.,31.7245961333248,-4.50857646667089));
#1406=VERTEX_POINT('',#1405);
#1407=CARTESIAN_POINT('',(0.,31.7245961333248,4.5085764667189));
#1408=VERTEX_POINT('',#1407);
#1409=EDGE_CURVE('P1_E174',#1406,#1408,#1404,.T.);
#1410=ORIENTED_EDGE('',*,*,#1409,.F.);
#1411=CARTESIAN_POINT('',(0.,31.7245961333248,0.));
#1412=DIRECTION('',(0.,-1.,0.));
#1413=DIRECTION('',(1.,0.,0.));
#1414=AXIS2_PLACEMENT_3D('',#1411,#1412,#1413);
#1415=CIRCLE('',#1414,4.50857646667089);
#1416=EDGE_CURVE('P1_E170',#1408,#1406,#1415,.T.);
#1417=ORIENTED_EDGE('',*,*,#1416,.F.);
#1418=DIRECTION('',(0.,1.,0.));
#1419=VECTOR('',#1418,1.);
#1420=CARTESIAN_POINT('',(0.,32.1690961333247,4.5085764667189));
#1421=LINE('',#1420,#1419);
#1422=EDGE_CURVE('P1_E242',#1408,#1373,#1421,.T.);
#1423=ORIENTED_EDGE('',*,*,#1422,.T.);
#1424=ORIENTED_EDGE('',*,*,#1381,.T.);
#1425=ORIENTED_EDGE('',*,*,#1374,.T.);
#1426=ORIENTED_EDGE('',*,*,#1422,.F.);
#1427=EDGE_LOOP('',(#1410,#1417,#1423,#1424,#1425,#1426));
#1428=FACE_BOUND('',#1427,.T.);
#1429=ADVANCED_FACE('P1_F18',(#1428),#1399,.T.);
#1430=CARTESIAN_POINT('',(0.,31.7245961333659,-4.12750000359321));
#1431=DIRECTION('',(0.,-1.,0.));
#1432=DIRECTION('',(0.,0.,-1.));
#1433=AXIS2_PLACEMENT_3D('',#1430,#1431,#1432);
#1434=PLANE('',#1433);
#1435=ORIENTED_EDGE('',*,*,#1409,.T.);
#1436=ORIENTED_EDGE('',*,*,#1416,.T.);
#1437=EDGE_LOOP('',(#1435,#1436));
#1438=FACE_BOUND('',#1437,.T.);
#1439=CARTESIAN_POINT('',(0.,31.7245961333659,0.));
#1440=DIRECTION('',(0.,-1.,0.));
#1441=DIRECTION('',(1.,0.,0.));
#1442=AXIS2_PLACEMENT_3D('',#1439,#1440,#1441);
#1443=CIRCLE('',#1442,4.12750000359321);
#1444=CARTESIAN_POINT('',(0.,31.7245961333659,-4.12750000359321));
#1445=VERTEX_POINT('',#1444);
#1446=CARTESIAN_POINT('',(0.,31.7245961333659,4.12750000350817));
#1447=VERTEX_POINT('',#1446);
#1448=EDGE_CURVE('P1_E192',#1445,#1447,#1443,.T.);
#1449=ORIENTED_EDGE('',*,*,#1448,.F.);
#1450=CARTESIAN_POINT('',(0.,31.7245961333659,0.));
#1451=DIRECTION('',(0.,-1.,0.));
#1452=DIRECTION('',(1.,0.,0.));
#1453=AXIS2_PLACEMENT_3D('',#1450,#1451,#1452);
#1454=CIRCLE('',#1453,4.12750000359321);
#1455=EDGE_CURVE('P1_E306',#1447,#1445,#1454,.T.);
#1456=ORIENTED_EDGE('',*,*,#1455,.F.);
#1457=EDGE_LOOP('',(#1449,#1456));
#1458=FACE_BOUND('',#1457,.T.);
#1459=ADVANCED_FACE('P1_F708',(#1438,#1458),#1434,.T.);
#1460=CARTESIAN_POINT('',(0.,30.937198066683,0.));
#1461=DIRECTION('',(0.,-1.,0.));
#1462=DIRECTION('',(0.,0.,-1.));
#1463=AXIS2_PLACEMENT_3D('',#1460,#1461,#1462);
#1464=CYLINDRICAL_SURFACE('',#1463,4.12750000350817);
#1465=ORIENTED_EDGE('',*,*,#829,.F.);
#1466=ORIENTED_EDGE('',*,*,#836,.F.);
#1467=DIRECTION('',(0.,1.,0.));
#1468=VECTOR('',#1467,1.);
#1469=CARTESIAN_POINT('',(0.,30.937198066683,4.12750000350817));
#1470=LINE('',#1469,#1468);
#1471=EDGE_CURVE('P1_E175',#828,#1447,#1470,.T.);
#1472=ORIENTED_EDGE('',*,*,#1471,.T.);
#1473=ORIENTED_EDGE('',*,*,#1455,.T.);
#1474=ORIENTED_EDGE('',*,*,#1448,.T.);
#1475=ORIENTED_EDGE('',*,*,#1471,.F.);
#1476=EDGE_LOOP('',(#1465,#1466,#1472,#1473,#1474,#1475));
#1477=FACE_BOUND('',#1476,.T.);
#1478=ADVANCED_FACE('P1_F704',(#1477),#1464,.T.);
#1479=CARTESIAN_POINT('',(0.,15.24,-6.35));
#1480=DIRECTION('',(0.,-1.,0.));
#1481=DIRECTION('',(0.,0.,-1.));
#1482=AXIS2_PLACEMENT_3D('',#1479,#1480,#1481);
#1483=PLANE('',#1482);
#1484=ORIENTED_EDGE('',*,*,#864,.T.);
#1485=ORIENTED_EDGE('',*,*,#871,.T.);
#1486=EDGE_LOOP('',(#1484,#1485));
#1487=FACE_BOUND('',#1486,.T.);
#1488=CARTESIAN_POINT('',(0.,15.24,0.));
#1489=DIRECTION('',(0.,-1.,0.));
#1490=DIRECTION('',(1.,0.,0.));
#1491=AXIS2_PLACEMENT_3D('',#1488,#1489,#1490);
#1492=CIRCLE('',#1491,6.35);
#1493=CARTESIAN_POINT('',(0.,15.24,-6.35));
#1494=VERTEX_POINT('',#1493);
#1495=CARTESIAN_POINT('',(0.,15.24,6.35));
#1496=VERTEX_POINT('',#1495);
#1497=EDGE_CURVE('P1_E259',#1494,#1496,#1492,.T.);
#1498=ORIENTED_EDGE('',*,*,#1497,.F.);
#1499=CARTESIAN_POINT('',(0.,15.24,0.));
#1500=DIRECTION('',(0.,-1.,0.));
#1501=DIRECTION('',(1.,0.,0.));
#1502=AXIS2_PLACEMENT_3D('',#1499,#1500,#1501);
#1503=CIRCLE('',#1502,6.35);
#1504=EDGE_CURVE('P1_E263',#1496,#1494,#1503,.T.);
#1505=ORIENTED_EDGE('',*,*,#1504,.F.);
#1506=EDGE_LOOP('',(#1498,#1505));
#1507=FACE_BOUND('',#1506,.T.);
#1508=ADVANCED_FACE('P1_F707',(#1487,#1507),#1483,.T.);
#1509=CARTESIAN_POINT('',(0.,7.62,0.));
#1510=DIRECTION('',(0.,-1.,0.));
#1511=DIRECTION('',(0.,0.,-1.));
#1512=AXIS2_PLACEMENT_3D('',#1509,#1510,#1511);
#1513=CYLINDRICAL_SURFACE('',#1512,6.35);
#1514=ORIENTED_EDGE('',*,*,#945,.F.);
#1515=ORIENTED_EDGE('',*,*,#952,.F.);
#1516=DIRECTION('',(0.,1.,0.));
#1517=VECTOR('',#1516,1.);
#1518=CARTESIAN_POINT('',(0.,7.62,6.35));
#1519=LINE('',#1518,#1517);
#1520=EDGE_CURVE('P1_E325',#944,#1496,#1519,.T.);
#1521=ORIENTED_EDGE('',*,*,#1520,.T.);
#1522=ORIENTED_EDGE('',*,*,#1504,.T.);
#1523=ORIENTED_EDGE('',*,*,#1497,.T.);
#1524=ORIENTED_EDGE('',*,*,#1520,.F.);
#1525=EDGE_LOOP('',(#1514,#1515,#1521,#1522,#1523,#1524));
#1526=FACE_BOUND('',#1525,.T.);
#1527=ADVANCED_FACE('P1_F666',(#1526),#1513,.T.);
#1528=CARTESIAN_POINT('',(0.,8.19974058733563,0.));
#1529=DIRECTION('',(0.,1.,0.));
#1530=DIRECTION('',(0.,0.,-1.));
#1531=AXIS2_PLACEMENT_3D('',#1528,#1529,#1530);
#1532=CONICAL_SURFACE('',#1531,4.91490022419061,1.04719741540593);
#1533=ORIENTED_EDGE('',*,*,#982,.T.);
#1534=DIRECTION('',(0.,0.500000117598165,0.866025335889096));
#1535=VECTOR('',#1534,1.);
#1536=CARTESIAN_POINT('',(0.,8.19974058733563,4.91490022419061));
#1537=LINE('',#1536,#1535);
#1538=CARTESIAN_POINT('',(0.,8.28039657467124,5.05460044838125));
#1539=VERTEX_POINT('',#1538);
#1540=EDGE_CURVE('P1_E237',#972,#1539,#1537,.T.);
#1541=ORIENTED_EDGE('',*,*,#1540,.T.);
#1542=CARTESIAN_POINT('',(0.,8.28039657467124,0.));
#1543=DIRECTION('',(0.,-1.,0.));
#1544=DIRECTION('',(1.,0.,0.));
#1545=AXIS2_PLACEMENT_3D('',#1542,#1543,#1544);
#1546=CIRCLE('',#1545,5.05460044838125);
#1547=CARTESIAN_POINT('',(0.,8.28039657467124,-5.05460044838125));
#1548=VERTEX_POINT('',#1547);
#1549=EDGE_CURVE('P1_E194',#1548,#1539,#1546,.T.);
#1550=ORIENTED_EDGE('',*,*,#1549,.F.);
#1551=CARTESIAN_POINT('',(0.,8.28039657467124,0.));
#1552=DIRECTION('',(0.,-1.,0.));
#1553=DIRECTION('',(1.,0.,0.));
#1554=AXIS2_PLACEMENT_3D('',#1551,#1552,#1553);
#1555=CIRCLE('',#1554,5.05460044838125);
#1556=EDGE_CURVE('P1_E210',#1539,#1548,#1555,.T.);
#1557=ORIENTED_EDGE('',*,*,#1556,.F.);
#1558=ORIENTED_EDGE('',*,*,#1540,.F.);
#1559=ORIENTED_EDGE('',*,*,#989,.T.);
#1560=EDGE_LOOP('',(#1533,#1541,#1550,#1557,#1558,#1559));
#1561=FACE_BOUND('',#1560,.T.);
#1562=ADVANCED_FACE('P1_F672',(#1561),#1532,.F.);
#1563=CARTESIAN_POINT('',(0.,8.7391219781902,0.));
#1564=DIRECTION('',(0.,-1.,0.));
#1565=DIRECTION('',(0.,0.,-1.));
#1566=AXIS2_PLACEMENT_3D('',#1563,#1564,#1565);
#1567=CYLINDRICAL_SURFACE('',#1566,5.05460038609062);
#1568=ORIENTED_EDGE('',*,*,#1549,.T.);
#1569=DIRECTION('',(0.,1.,0.));
#1570=VECTOR('',#1569,1.);
#1571=CARTESIAN_POINT('',(0.,8.7391219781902,5.05460038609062));
#1572=LINE('',#1571,#1570);
#1573=CARTESIAN_POINT('',(0.,9.19784738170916,5.05460038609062));
#1574=VERTEX_POINT('',#1573);
#1575=EDGE_CURVE('P1_E199',#1539,#1574,#1572,.T.);
#1576=ORIENTED_EDGE('',*,*,#1575,.T.);
#1577=CARTESIAN_POINT('',(0.,9.19784738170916,0.));
#1578=DIRECTION('',(0.,-1.,0.));
#1579=DIRECTION('',(1.,0.,0.));
#1580=AXIS2_PLACEMENT_3D('',#1577,#1578,#1579);
#1581=CIRCLE('',#1580,5.05460032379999);
#1582=CARTESIAN_POINT('',(0.,9.19784738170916,-5.05460032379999));
#1583=VERTEX_POINT('',#1582);
#1584=EDGE_CURVE('P1_E204',#1583,#1574,#1581,.T.);
#1585=ORIENTED_EDGE('',*,*,#1584,.F.);
#1586=CARTESIAN_POINT('',(0.,9.19784738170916,0.));
#1587=DIRECTION('',(0.,-1.,0.));
#1588=DIRECTION('',(1.,0.,0.));
#1589=AXIS2_PLACEMENT_3D('',#1586,#1587,#1588);
#1590=CIRCLE('',#1589,5.05460032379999);
#1591=EDGE_CURVE('P1_E205',#1574,#1583,#1590,.T.);
#1592=ORIENTED_EDGE('',*,*,#1591,.F.);
#1593=ORIENTED_EDGE('',*,*,#1575,.F.);
#1594=ORIENTED_EDGE('',*,*,#1556,.T.);
#1595=EDGE_LOOP('',(#1568,#1576,#1585,#1592,#1593,#1594));
#1596=FACE_BOUND('',#1595,.T.);
#1597=ADVANCED_FACE('P1_F668',(#1596),#1567,.F.);
#1598=CARTESIAN_POINT('',(0.,9.35256267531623,0.));
#1599=DIRECTION('',(0.,1.,0.));
#1600=DIRECTION('',(0.,0.,-1.));
#1601=AXIS2_PLACEMENT_3D('',#1598,#1599,#1600);
#1602=CONICAL_SURFACE('',#1601,5.25780016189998,0.920042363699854);
#1603=ORIENTED_EDGE('',*,*,#1584,.T.);
#1604=DIRECTION('',(0.,0.605786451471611,0.795627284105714));
#1605=VECTOR('',#1604,1.);
#1606=CARTESIAN_POINT('',(0.,9.35256267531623,5.25780016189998));
#1607=LINE('',#1606,#1605);
#1608=CARTESIAN_POINT('',(0.,9.50727796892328,5.461));
#1609=VERTEX_POINT('',#1608);
#1610=EDGE_CURVE('P1_E200',#1574,#1609,#1607,.T.);
#1611=ORIENTED_EDGE('',*,*,#1610,.T.);
#1612=CARTESIAN_POINT('',(0.,9.50727796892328,0.));
#1613=DIRECTION('',(0.,-1.,0.));
#1614=DIRECTION('',(1.,0.,0.));
#1615=AXIS2_PLACEMENT_3D('',#1612,#1613,#1614);
#1616=CIRCLE('',#1615,5.461);
#1617=CARTESIAN_POINT('',(0.,9.50727796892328,-5.461));
#1618=VERTEX_POINT('',#1617);
#1619=EDGE_CURVE('P1_E276',#1618,#1609,#1616,.T.);
#1620=ORIENTED_EDGE('',*,*,#1619,.F.);
#1621=CARTESIAN_POINT('',(0.,9.50727796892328,0.));
#1622=DIRECTION('',(0.,-1.,0.));
#1623=DIRECTION('',(1.,0.,0.));
#1624=AXIS2_PLACEMENT_3D('',#1621,#1622,#1623);
#1625=CIRCLE('',#1624,5.461);
#1626=EDGE_CURVE('P1_E224',#1609,#1618,#1625,.T.);
#1627=ORIENTED_EDGE('',*,*,#1626,.F.);
#1628=ORIENTED_EDGE('',*,*,#1610,.F.);
#1629=ORIENTED_EDGE('',*,*,#1591,.T.);
#1630=EDGE_LOOP('',(#1603,#1611,#1620,#1627,#1628,#1629));
#1631=FACE_BOUND('',#1630,.T.);
#1632=ADVANCED_FACE('P1_F671',(#1631),#1602,.F.);
#1633=CARTESIAN_POINT('',(0.,10.4597779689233,0.));
#1634=DIRECTION('',(0.,-1.,0.));
#1635=DIRECTION('',(0.,0.,-1.));
#1636=AXIS2_PLACEMENT_3D('',#1633,#1634,#1635);
#1637=CYLINDRICAL_SURFACE('',#1636,5.461);
#1638=ORIENTED_EDGE('',*,*,#1619,.T.);
#1639=DIRECTION('',(0.,1.,0.));
#1640=VECTOR('',#1639,1.);
#1641=CARTESIAN_POINT('',(0.,10.4597779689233,5.461));
#1642=LINE('',#1641,#1640);
#1643=CARTESIAN_POINT('',(0.,11.4122779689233,5.461));
#1644=VERTEX_POINT('',#1643);
#1645=EDGE_CURVE('P1_E258',#1609,#1644,#1642,.T.);
#1646=ORIENTED_EDGE('',*,*,#1645,.T.);
#1647=CARTESIAN_POINT('',(0.,11.4122779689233,0.));
#1648=DIRECTION('',(0.,-1.,0.));
#1649=DIRECTION('',(1.,0.,0.));
#1650=AXIS2_PLACEMENT_3D('',#1647,#1648,#1649);
#1651=CIRCLE('',#1650,5.461);
#1652=CARTESIAN_POINT('',(0.,11.4122779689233,-5.461));
#1653=VERTEX_POINT('',#1652);
#1654=EDGE_CURVE('P1_E220',#1653,#1644,#1651,.T.);
#1655=ORIENTED_EDGE('',*,*,#1654,.F.);
#1656=CARTESIAN_POINT('',(0.,11.4122779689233,0.));
#1657=DIRECTION('',(0.,-1.,0.));
#1658=DIRECTION('',(1.,0.,0.));
#1659=AXIS2_PLACEMENT_3D('',#1656,#1657,#1658);
#1660=CIRCLE('',#1659,5.461);
#1661=EDGE_CURVE('P1_E286',#1644,#1653,#1660,.T.);
#1662=ORIENTED_EDGE('',*,*,#1661,.F.);
#1663=ORIENTED_EDGE('',*,*,#1645,.F.);
#1664=ORIENTED_EDGE('',*,*,#1626,.T.);
#1665=EDGE_LOOP('',(#1638,#1646,#1655,#1662,#1663,#1664));
#1666=FACE_BOUND('',#1665,.T.);
#1667=ADVANCED_FACE('P1_F676',(#1666),#1637,.F.);
#1668=CARTESIAN_POINT('',(0.,11.4973389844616,0.));
#1669=DIRECTION('',(0.,-1.,0.));
#1670=DIRECTION('',(0.,0.,-1.));
#1671=AXIS2_PLACEMENT_3D('',#1668,#1669,#1670);
#1672=CONICAL_SURFACE('',#1671,5.2578,1.17435273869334);
#1673=ORIENTED_EDGE('',*,*,#1654,.T.);
#1674=DIRECTION('',(0.,0.386140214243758,-0.922440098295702));
#1675=VECTOR('',#1674,1.);
#1676=CARTESIAN_POINT('',(0.,11.4973389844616,5.2578));
#1677=LINE('',#1676,#1675);
#1678=CARTESIAN_POINT('',(0.,11.5824,5.0546));
#1679=VERTEX_POINT('',#1678);
#1680=EDGE_CURVE('P1_E225',#1644,#1679,#1677,.T.);
#1681=ORIENTED_EDGE('',*,*,#1680,.T.);
#1682=CARTESIAN_POINT('',(0.,11.5824,0.));
#1683=DIRECTION('',(0.,-1.,0.));
#1684=DIRECTION('',(1.,0.,0.));
#1685=AXIS2_PLACEMENT_3D('',#1682,#1683,#1684);
#1686=CIRCLE('',#1685,5.0546);
#1687=CARTESIAN_POINT('',(0.,11.5824,-5.0546));
#1688=VERTEX_POINT('',#1687);
#1689=EDGE_CURVE('P1_E290',#1688,#1679,#1686,.T.);
#1690=ORIENTED_EDGE('',*,*,#1689,.F.);
#1691=CARTESIAN_POINT('',(0.,11.5824,0.));
#1692=DIRECTION('',(0.,-1.,0.));
#1693=DIRECTION('',(1.,0.,0.));
#1694=AXIS2_PLACEMENT_3D('',#1691,#1692,#1693);
#1695=CIRCLE('',#1694,5.0546);
#1696=EDGE_CURVE('P1_E377',#1679,#1688,#1695,.T.);
#1697=ORIENTED_EDGE('',*,*,#1696,.F.);
#1698=ORIENTED_EDGE('',*,*,#1680,.F.);
#1699=ORIENTED_EDGE('',*,*,#1661,.T.);
#1700=EDGE_LOOP('',(#1673,#1681,#1690,#1697,#1698,#1699));
#1701=FACE_BOUND('',#1700,.T.);
#1702=ADVANCED_FACE('P1_F680',(#1701),#1672,.F.);
#1703=CARTESIAN_POINT('',(0.,12.2174,0.));
#1704=DIRECTION('',(0.,-1.,0.));
#1705=DIRECTION('',(0.,0.,-1.));
#1706=AXIS2_PLACEMENT_3D('',#1703,#1704,#1705);
#1707=CYLINDRICAL_SURFACE('',#1706,5.0546);
#1708=ORIENTED_EDGE('',*,*,#1689,.T.);
#1709=DIRECTION('',(0.,1.,0.));
#1710=VECTOR('',#1709,1.);
#1711=CARTESIAN_POINT('',(0.,12.2174,5.0546));
#1712=LINE('',#1711,#1710);
#1713=EDGE_CURVE('P1_E316',#1679,#1008,#1712,.T.);
#1714=ORIENTED_EDGE('',*,*,#1713,.T.);
#1715=ORIENTED_EDGE('',*,*,#1009,.F.);
#1716=ORIENTED_EDGE('',*,*,#1016,.F.);
#1717=ORIENTED_EDGE('',*,*,#1713,.F.);
#1718=ORIENTED_EDGE('',*,*,#1696,.T.);
#1719=EDGE_LOOP('',(#1708,#1714,#1715,#1716,#1717,#1718));
#1720=FACE_BOUND('',#1719,.T.);
#1721=ADVANCED_FACE('P1_F721',(#1720),#1707,.F.);
#1722=CLOSED_SHELL('',(#622,#652,#687,#723,#758,#810,#840,#888,#930,#959,#994,#1040,#1075,#1089,
#1124,#1159,#1189,#1224,#1259,#1294,#1324,#1359,#1394,#1429,#1459,#1478,#1508,#1527,#1562,#1597,
#1632,#1667,#1702,#1721));
#1723=MANIFOLD_SOLID_BREP('P1_B1',#1722);
#1724=CARTESIAN_POINT('',(0.,10.6299000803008,0.));
#1725=DIRECTION('',(0.,-1.,0.));
#1726=DIRECTION('',(0.,0.,-1.));
#1727=AXIS2_PLACEMENT_3D('',#1724,#1725,#1726);
#1728=CYLINDRICAL_SURFACE('',#1727,4.9022);
#1729=CARTESIAN_POINT('',(0.,8.40740008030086,0.));
#1730=DIRECTION('',(0.,-1.,0.));
#1731=DIRECTION('',(1.,0.,0.));
#1732=AXIS2_PLACEMENT_3D('',#1729,#1730,#1731);
#1733=CIRCLE('',#1732,4.9022);
#1734=CARTESIAN_POINT('',(0.,8.40740008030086,-4.9022));
#1735=VERTEX_POINT('',#1734);
#1736=CARTESIAN_POINT('',(0.,8.40740008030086,4.9022));
#1737=VERTEX_POINT('',#1736);
#1738=EDGE_CURVE('P2_E38',#1735,#1737,#1733,.T.);
#1739=ORIENTED_EDGE('',*,*,#1738,.F.);
#1740=CARTESIAN_POINT('',(0.,8.40740008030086,0.));
#1741=DIRECTION('',(0.,-1.,0.));
#1742=DIRECTION('',(1.,0.,0.));
#1743=AXIS2_PLACEMENT_3D('',#1740,#1741,#1742);
#1744=CIRCLE('',#1743,4.9022);
#1745=EDGE_CURVE('P2_E76',#1737,#1735,#1744,.T.);
#1746=ORIENTED_EDGE('',*,*,#1745,.F.);
#1747=DIRECTION('',(0.,1.,0.));
#1748=VECTOR('',#1747,1.);
#1749=CARTESIAN_POINT('',(0.,10.6299000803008,4.9022));
#1750=LINE('',#1749,#1748);
#1751=CARTESIAN_POINT('',(0.,12.8524000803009,4.9022));
#1752=VERTEX_POINT('',#1751);
#1753=EDGE_CURVE('P2_E11',#1737,#1752,#1750,.T.);
#1754=ORIENTED_EDGE('',*,*,#1753,.T.);
#1755=CARTESIAN_POINT('',(0.,12.8524000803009,0.));
#1756=DIRECTION('',(0.,-1.,0.));
#1757=DIRECTION('',(1.,0.,0.));
#1758=AXIS2_PLACEMENT_3D('',#1755,#1756,#1757);
#1759=CIRCLE('',#1758,4.9022);
#1760=CARTESIAN_POINT('',(0.,12.8524000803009,-4.9022));
#1761=VERTEX_POINT('',#1760);
#1762=EDGE_CURVE('P2_E26',#1752,#1761,#1759,.T.);
#1763=ORIENTED_EDGE('',*,*,#1762,.T.);
#1764=CARTESIAN_POINT('',(0.,12.8524000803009,0.));
#1765=DIRECTION('',(0.,-1.,0.));
#1766=DIRECTION('',(1.,0.,0.));
#1767=AXIS2_PLACEMENT_3D('',#1764,#1765,#1766);
#1768=CIRCLE('',#1767,4.9022);
#1769=EDGE_CURVE('P2_E99',#1761,#1752,#1768,.T.);
#1770=ORIENTED_EDGE('',*,*,#1769,.T.);
#1771=ORIENTED_EDGE('',*,*,#1753,.F.);
#1772=EDGE_LOOP('',(#1739,#1746,#1754,#1763,#1770,#1771));
#1773=FACE_BOUND('',#1772,.T.);
#1774=ADVANCED_FACE('P2_F16',(#1773),#1728,.T.);
#1775=CARTESIAN_POINT('',(0.,8.40740008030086,-3.5052));
#1776=DIRECTION('',(0.,-1.,0.));
#1777=DIRECTION('',(0.,0.,-1.));
#1778=AXIS2_PLACEMENT_3D('',#1775,#1776,#1777);
#1779=PLANE('',#1778);
#1780=ORIENTED_EDGE('',*,*,#1738,.T.);
#1781=ORIENTED_EDGE('',*,*,#1745,.T.);
#1782=EDGE_LOOP('',(#1780,#1781));
#1783=FACE_BOUND('',#1782,.T.);
#1784=CARTESIAN_POINT('',(0.,8.40740008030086,0.));
#1785=DIRECTION('',(0.,-1.,0.));
#1786=DIRECTION('',(1.,0.,0.));
#1787=AXIS2_PLACEMENT_3D('',#1784,#1785,#1786);
#1788=CIRCLE('',#1787,3.5052);
#1789=CARTESIAN_POINT('',(0.,8.40740008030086,-3.5052));
#1790=VERTEX_POINT('',#1789);
#1791=CARTESIAN_POINT('',(0.,8.40740008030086,3.5052));
#1792=VERTEX_POINT('',#1791);
#1793=EDGE_CURVE('P2_E68',#1790,#1792,#1788,.T.);
#1794=ORIENTED_EDGE('',*,*,#1793,.F.);
#1795=CARTESIAN_POINT('',(0.,8.40740008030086,0.));
#1796=DIRECTION('',(0.,-1.,0.));
#1797=DIRECTION('',(1.,0.,0.));
#1798=AXIS2_PLACEMENT_3D('',#1795,#1796,#1797);
#1799=CIRCLE('',#1798,3.5052);
#1800=EDGE_CURVE('P2_E71',#1792,#1790,#1799,.T.);
#1801=ORIENTED_EDGE('',*,*,#1800,.F.);
#1802=EDGE_LOOP('',(#1794,#1801));
#1803=FACE_BOUND('',#1802,.T.);
#1804=ADVANCED_FACE('P2_F70',(#1783,#1803),#1779,.T.);
#1805=CARTESIAN_POINT('',(0.,10.6299000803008,0.));
#1806=DIRECTION('',(0.,-1.,0.));
#1807=DIRECTION('',(0.,0.,-1.));
#1808=AXIS2_PLACEMENT_3D('',#1805,#1806,#1807);
#1809=CYLINDRICAL_SURFACE('',#1808,3.5052);
#1810=ORIENTED_EDGE('',*,*,#1793,.T.);
#1811=DIRECTION('',(0.,1.,0.));
#1812=VECTOR('',#1811,1.);
#1813=CARTESIAN_POINT('',(0.,10.6299000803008,3.5052));
#1814=LINE('',#1813,#1812);
#1815=CARTESIAN_POINT('',(0.,12.8524000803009,3.5052));
#1816=VERTEX_POINT('',#1815);
#1817=EDGE_CURVE('P2_E77',#1792,#1816,#1814,.T.);
#1818=ORIENTED_EDGE('',*,*,#1817,.T.);
#1819=CARTESIAN_POINT('',(0.,12.8524000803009,0.));
#1820=DIRECTION('',(0.,-1.,0.));
#1821=DIRECTION('',(1.,0.,0.));
#1822=AXIS2_PLACEMENT_3D('',#1819,#1820,#1821);
#1823=CIRCLE('',#1822,3.5052);
#1824=CARTESIAN_POINT('',(0.,12.8524000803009,-3.5052));
#1825=VERTEX_POINT('',#1824);
#1826=EDGE_CURVE('P2_E82',#1825,#1816,#1823,.T.);
#1827=ORIENTED_EDGE('',*,*,#1826,.F.);
#1828=CARTESIAN_POINT('',(0.,12.8524000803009,0.));
#1829=DIRECTION('',(0.,-1.,0.));
#1830=DIRECTION('',(1.,0.,0.));
#1831=AXIS2_PLACEMENT_3D('',#1828,#1829,#1830);
#1832=CIRCLE('',#1831,3.5052);
#1833=EDGE_CURVE('P2_E91',#1816,#1825,#1832,.T.);
#1834=ORIENTED_EDGE('',*,*,#1833,.F.);
#1835=ORIENTED_EDGE('',*,*,#1817,.F.);
#1836=ORIENTED_EDGE('',*,*,#1800,.T.);
#1837=EDGE_LOOP('',(#1810,#1818,#1827,#1834,#1835,#1836));
#1838=FACE_BOUND('',#1837,.T.);
#1839=ADVANCED_FACE('P2_F79',(#1838),#1809,.F.);
#1840=CARTESIAN_POINT('',(0.,12.8524000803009,-4.9022));
#1841=DIRECTION('',(0.,1.,0.));
#1842=DIRECTION('',(1.,0.,0.));
#1843=AXIS2_PLACEMENT_3D('',#1840,#1841,#1842);
#1844=PLANE('',#1843);
#1845=ORIENTED_EDGE('',*,*,#1769,.F.);
#1846=ORIENTED_EDGE('',*,*,#1762,.F.);
#1847=EDGE_LOOP('',(#1845,#1846));
#1848=FACE_BOUND('',#1847,.T.);
#1849=ORIENTED_EDGE('',*,*,#1826,.T.);
#1850=ORIENTED_EDGE('',*,*,#1833,.T.);
#1851=EDGE_LOOP('',(#1849,#1850));
#1852=FACE_BOUND('',#1851,.T.);
#1853=ADVANCED_FACE('P2_F18',(#1848,#1852),#1844,.T.);
#1854=CLOSED_SHELL('',(#1774,#1804,#1839,#1853));
#1855=MANIFOLD_SOLID_BREP('P2_B1',#1854);
#1856=CARTESIAN_POINT('',(0.,30.1498,-4.1656));
#1857=DIRECTION('',(0.,-1.,0.));
#1858=DIRECTION('',(0.,0.,-1.));
#1859=AXIS2_PLACEMENT_3D('',#1856,#1857,#1858);
#1860=PLANE('',#1859);
#1861=CARTESIAN_POINT('',(0.,30.1498,0.));
#1862=DIRECTION('',(0.,-1.,0.));
#1863=DIRECTION('',(1.,0.,0.));
#1864=AXIS2_PLACEMENT_3D('',#1861,#1862,#1863);
#1865=CIRCLE('',#1864,8.7249);
#1866=CARTESIAN_POINT('',(0.,30.1498,-8.7249));
#1867=VERTEX_POINT('',#1866);
#1868=CARTESIAN_POINT('',(0.,30.1498,8.7249));
#1869=VERTEX_POINT('',#1868);
#1870=EDGE_CURVE('P3_E10',#1867,#1869,#1865,.T.);
#1871=ORIENTED_EDGE('',*,*,#1870,.T.);
#1872=CARTESIAN_POINT('',(0.,30.1498,0.));
#1873=DIRECTION('',(0.,-1.,0.));
#1874=DIRECTION('',(1.,0.,0.));
#1875=AXIS2_PLACEMENT_3D('',#1872,#1873,#1874);
#1876=CIRCLE('',#1875,8.7249);
#1877=EDGE_CURVE('P3_E26',#1869,#1867,#1876,.T.);
#1878=ORIENTED_EDGE('',*,*,#1877,.T.);
#1879=EDGE_LOOP('',(#1871,#1878));
#1880=FACE_BOUND('',#1879,.T.);
#1881=CARTESIAN_POINT('',(0.,30.1498,0.));
#1882=DIRECTION('',(0.,-1.,0.));
#1883=DIRECTION('',(1.,0.,0.));
#1884=AXIS2_PLACEMENT_3D('',#1881,#1882,#1883);
#1885=CIRCLE('',#1884,4.1656);
#1886=CARTESIAN_POINT('',(0.,30.1498,-4.1656));
#1887=VERTEX_POINT('',#1886);
#1888=CARTESIAN_POINT('',(0.,30.1498,4.1656));
#1889=VERTEX_POINT('',#1888);
#1890=EDGE_CURVE('P3_E94',#1887,#1889,#1885,.T.);
#1891=ORIENTED_EDGE('',*,*,#1890,.F.);
#1892=CARTESIAN_POINT('',(0.,30.1498,0.));
#1893=DIRECTION('',(0.,-1.,0.));
#1894=DIRECTION('',(1.,0.,0.));
#1895=AXIS2_PLACEMENT_3D('',#1892,#1893,#1894);
#1896=CIRCLE('',#1895,4.1656);
#1897=EDGE_CURVE('P3_E92',#1889,#1887,#1896,.T.);
#1898=ORIENTED_EDGE('',*,*,#1897,.F.);
#1899=EDGE_LOOP('',(#1891,#1898));
#1900=FACE_BOUND('',#1899,.T.);
#1901=ADVANCED_FACE('P3_F15',(#1880,#1900),#1860,.T.);
#1902=CARTESIAN_POINT('',(0.,30.7848,0.));
#1903=DIRECTION('',(0.,-1.,0.));
#1904=DIRECTION('',(0.,0.,-1.));
#1905=AXIS2_PLACEMENT_3D('',#1902,#1903,#1904);
#1906=CYLINDRICAL_SURFACE('',#1905,4.1656);
#1907=ORIENTED_EDGE('',*,*,#1890,.T.);
#1908=DIRECTION('',(0.,1.,0.));
#1909=VECTOR('',#1908,1.);
#1910=CARTESIAN_POINT('',(0.,30.7848,4.1656));
#1911=LINE('',#1910,#1909);
#1912=CARTESIAN_POINT('',(0.,31.4198,4.1656));
#1913=VERTEX_POINT('',#1912);
#1914=EDGE_CURVE('P3_E98',#1889,#1913,#1911,.T.);
#1915=ORIENTED_EDGE('',*,*,#1914,.T.);
#1916=CARTESIAN_POINT('',(0.,31.4198,0.));
#1917=DIRECTION('',(0.,-1.,0.));
#1918=DIRECTION('',(1.,0.,0.));
#1919=AXIS2_PLACEMENT_3D('',#1916,#1917,#1918);
#1920=CIRCLE('',#1919,4.1656);
#1921=CARTESIAN_POINT('',(0.,31.4198,-4.1656));
#1922=VERTEX_POINT('',#1921);
#1923=EDGE_CURVE('P3_E86',#1922,#1913,#1920,.T.);
#1924=ORIENTED_EDGE('',*,*,#1923,.F.);
#1925=CARTESIAN_POINT('',(0.,31.4198,0.));
#1926=DIRECTION('',(0.,-1.,0.));
#1927=DIRECTION('',(1.,0.,0.));
#1928=AXIS2_PLACEMENT_3D('',#1925,#1926,#1927);
#1929=CIRCLE('',#1928,4.1656);
#1930=EDGE_CURVE('P3_E104',#1913,#1922,#1929,.T.);
#1931=ORIENTED_EDGE('',*,*,#1930,.F.);
#1932=ORIENTED_EDGE('',*,*,#1914,.F.);
#1933=ORIENTED_EDGE('',*,*,#1897,.T.);
#1934=EDGE_LOOP('',(#1907,#1915,#1924,#1931,#1932,#1933));
#1935=FACE_BOUND('',#1934,.T.);
#1936=ADVANCED_FACE('P3_F100',(#1935),#1906,.F.);
#1937=CARTESIAN_POINT('',(0.,31.4198,-7.4549));
#1938=DIRECTION('',(0.,1.,0.));
#1939=DIRECTION('',(1.,0.,0.));
#1940=AXIS2_PLACEMENT_3D('',#1937,#1938,#1939);
#1941=PLANE('',#1940);
#1942=CARTESIAN_POINT('',(0.,31.4198,0.));
#1943=DIRECTION('',(0.,-1.,0.));
#1944=DIRECTION('',(1.,0.,0.));
#1945=AXIS2_PLACEMENT_3D('',#1942,#1943,#1944);
#1946=CIRCLE('',#1945,7.4549);
#1947=CARTESIAN_POINT('',(0.,31.4198,-7.4549));
#1948=VERTEX_POINT('',#1947);
#1949=CARTESIAN_POINT('',(0.,31.4198,7.4549));
#1950=VERTEX_POINT('',#1949);
#1951=EDGE_CURVE('P3_E120',#1948,#1950,#1946,.T.);
#1952=ORIENTED_EDGE('',*,*,#1951,.F.);
#1953=CARTESIAN_POINT('',(0.,31.4198,0.));
#1954=DIRECTION('',(0.,-1.,0.));
#1955=DIRECTION('',(1.,0.,0.));
#1956=AXIS2_PLACEMENT_3D('',#1953,#1954,#1955);
#1957=CIRCLE('',#1956,7.4549);
#1958=EDGE_CURVE('P3_E117',#1950,#1948,#1957,.T.);
#1959=ORIENTED_EDGE('',*,*,#1958,.F.);
#1960=EDGE_LOOP('',(#1952,#1959));
#1961=FACE_BOUND('',#1960,.T.);
#1962=ORIENTED_EDGE('',*,*,#1923,.T.);
#1963=ORIENTED_EDGE('',*,*,#1930,.T.);
#1964=EDGE_LOOP('',(#1962,#1963));
#1965=FACE_BOUND('',#1964,.T.);
#1966=ADVANCED_FACE('P3_F155',(#1961,#1965),#1941,.T.);
#1967=CARTESIAN_POINT('',(0.,33.0073,0.));
#1968=DIRECTION('',(0.,-1.,0.));
#1969=DIRECTION('',(0.,0.,-1.));
#1970=AXIS2_PLACEMENT_3D('',#1967,#1968,#1969);
#1971=CYLINDRICAL_SURFACE('',#1970,7.4549);
#1972=ORIENTED_EDGE('',*,*,#1951,.T.);
#1973=DIRECTION('',(0.,1.,0.));
#1974=VECTOR('',#1973,1.);
#1975=CARTESIAN_POINT('',(0.,33.0073,7.4549));
#1976=LINE('',#1975,#1974);
#1977=CARTESIAN_POINT('',(0.,34.5948,7.4549));
#1978=VERTEX_POINT('',#1977);
#1979=EDGE_CURVE('P3_E19',#1950,#1978,#1976,.T.);
#1980=ORIENTED_EDGE('',*,*,#1979,.T.);
#1981=CARTESIAN_POINT('',(0.,34.5948,0.));
#1982=DIRECTION('',(0.,-1.,0.));
#1983=DIRECTION('',(1.,0.,0.));
#1984=AXIS2_PLACEMENT_3D('',#1981,#1982,#1983);
#1985=CIRCLE('',#1984,7.4549);
#1986=CARTESIAN_POINT('',(0.,34.5948,-7.4549));
#1987=VERTEX_POINT('',#1986);
#1988=EDGE_CURVE('P3_E113',#1987,#1978,#1985,.T.);
#1989=ORIENTED_EDGE('',*,*,#1988,.F.);
#1990=CARTESIAN_POINT('',(0.,34.5948,0.));
#1991=DIRECTION('',(0.,-1.,0.));
#1992=DIRECTION('',(1.,0.,0.));
#1993=AXIS2_PLACEMENT_3D('',#1990,#1991,#1992);
#1994=CIRCLE('',#1993,7.4549);
#1995=EDGE_CURVE('P3_E110',#1978,#1987,#1994,.T.);
#1996=ORIENTED_EDGE('',*,*,#1995,.F.);
#1997=ORIENTED_EDGE('',*,*,#1979,.F.);
#1998=ORIENTED_EDGE('',*,*,#1958,.T.);
#1999=EDGE_LOOP('',(#1972,#1980,#1989,#1996,#1997,#1998));
#2000=FACE_BOUND('',#1999,.T.);
#2001=ADVANCED_FACE('P3_F145',(#2000),#1971,.F.);
#2002=CARTESIAN_POINT('',(0.,34.5948,-8.7249));
#2003=DIRECTION('',(0.,1.,0.));
#2004=DIRECTION('',(1.,0.,0.));
#2005=AXIS2_PLACEMENT_3D('',#2002,#2003,#2004);
#2006=PLANE('',#2005);
#2007=CARTESIAN_POINT('',(0.,34.5948,0.));
#2008=DIRECTION('',(0.,-1.,0.));
#2009=DIRECTION('',(1.,0.,0.));
#2010=AXIS2_PLACEMENT_3D('',#2007,#2008,#2009);
#2011=CIRCLE('',#2010,8.7249);
#2012=CARTESIAN_POINT('',(0.,34.5948,-8.7249));
#2013=VERTEX_POINT('',#2012);
#2014=CARTESIAN_POINT('',(0.,34.5948,8.7249));
#2015=VERTEX_POINT('',#2014);
#2016=EDGE_CURVE('P3_E74',#2013,#2015,#2011,.T.);
#2017=ORIENTED_EDGE('',*,*,#2016,.F.);
#2018=CARTESIAN_POINT('',(0.,34.5948,0.));
#2019=DIRECTION('',(0.,-1.,0.));
#2020=DIRECTION('',(1.,0.,0.));
#2021=AXIS2_PLACEMENT_3D('',#2018,#2019,#2020);
#2022=CIRCLE('',#2021,8.7249);
#2023=EDGE_CURVE('P3_E126',#2015,#2013,#2022,.T.);
#2024=ORIENTED_EDGE('',*,*,#2023,.F.);
#2025=EDGE_LOOP('',(#2017,#2024));
#2026=FACE_BOUND('',#2025,.T.);
#2027=ORIENTED_EDGE('',*,*,#1988,.T.);
#2028=ORIENTED_EDGE('',*,*,#1995,.T.);
#2029=EDGE_LOOP('',(#2027,#2028));
#2030=FACE_BOUND('',#2029,.T.);
#2031=ADVANCED_FACE('P3_F147',(#2026,#2030),#2006,.T.);
#2032=CARTESIAN_POINT('',(0.,32.3723,0.));
#2033=DIRECTION('',(0.,-1.,0.));
#2034=DIRECTION('',(0.,0.,-1.));
#2035=AXIS2_PLACEMENT_3D('',#2032,#2033,#2034);
#2036=CYLINDRICAL_SURFACE('',#2035,8.7249);
#2037=ORIENTED_EDGE('',*,*,#1870,.F.);
#2038=ORIENTED_EDGE('',*,*,#1877,.F.);
#2039=DIRECTION('',(0.,1.,0.));
#2040=VECTOR('',#2039,1.);
#2041=CARTESIAN_POINT('',(0.,32.3723,8.7249));
#2042=LINE('',#2041,#2040);
#2043=EDGE_CURVE('P3_E114',#1869,#2015,#2042,.T.);
#2044=ORIENTED_EDGE('',*,*,#2043,.T.);
#2045=ORIENTED_EDGE('',*,*,#2023,.T.);
#2046=ORIENTED_EDGE('',*,*,#2016,.T.);
#2047=ORIENTED_EDGE('',*,*,#2043,.F.);
#2048=EDGE_LOOP('',(#2037,#2038,#2044,#2045,#2046,#2047));
#2049=FACE_BOUND('',#2048,.T.);
#2050=ADVANCED_FACE('P3_F17',(#2049),#2036,.T.);
#2051=CLOSED_SHELL('',(#1901,#1936,#1966,#2001,#2031,#2050));
#2052=MANIFOLD_SOLID_BREP('P3_B1',#2051);
#2053=ADVANCED_BREP_SHAPE_REPRESENTATION('',(#18,#570,#1723,#1855,#2052),#14);
#2054=SHAPE_DEFINITION_REPRESENTATION(#9,#2053);
ENDSEC;
END-ISO-10303-21;
